VERSION 5.8 ;
BUSBITCHARS "[]" ;
DIVIDERCHAR "/" ;
UNITS
    DATABASE MICRONS 1000 ;
END UNITS

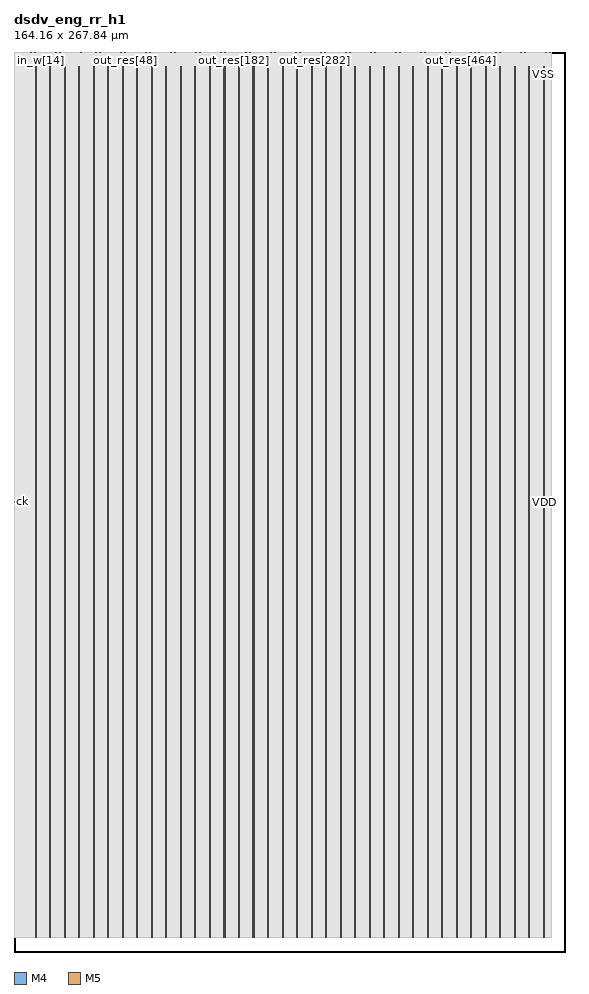
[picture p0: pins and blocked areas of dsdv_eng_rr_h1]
MACRO dsdv_eng_rr_h1
  FOREIGN dsdv_eng_rr_h1 0 0 ;
  CLASS BLOCK ;
  SIZE 164.16 BY 267.84 ;
  PIN ck
    DIRECTION INPUT ;
    USE SIGNAL ;
    PORT
      LAYER M4 ;
        RECT  0 133.92 0.084 133.944 ;
    END
  END ck
  PIN in_w[0]
    DIRECTION INPUT ;
    USE SIGNAL ;
    PORT
      LAYER M5 ;
        RECT  4.8 267.756 4.824 267.84 ;
    END
  END in_w[0]
  PIN in_w[10]
    DIRECTION INPUT ;
    USE SIGNAL ;
    PORT
      LAYER M5 ;
        RECT  7.2 267.756 7.224 267.84 ;
    END
  END in_w[10]
  PIN in_w[11]
    DIRECTION INPUT ;
    USE SIGNAL ;
    PORT
      LAYER M5 ;
        RECT  7.44 267.756 7.464 267.84 ;
    END
  END in_w[11]
  PIN in_w[12]
    DIRECTION INPUT ;
    USE SIGNAL ;
    PORT
      LAYER M5 ;
        RECT  7.68 267.756 7.704 267.84 ;
    END
  END in_w[12]
  PIN in_w[13]
    DIRECTION INPUT ;
    USE SIGNAL ;
    PORT
      LAYER M5 ;
        RECT  7.92 267.756 7.944 267.84 ;
    END
  END in_w[13]
  PIN in_w[14]
    DIRECTION INPUT ;
    USE SIGNAL ;
    PORT
      LAYER M5 ;
        RECT  8.16 267.756 8.184 267.84 ;
    END
  END in_w[14]
  PIN in_w[15]
    DIRECTION INPUT ;
    USE SIGNAL ;
    PORT
      LAYER M5 ;
        RECT  8.4 267.756 8.424 267.84 ;
    END
  END in_w[15]
  PIN in_w[16]
    DIRECTION INPUT ;
    USE SIGNAL ;
    PORT
      LAYER M5 ;
        RECT  8.64 267.756 8.664 267.84 ;
    END
  END in_w[16]
  PIN in_w[17]
    DIRECTION INPUT ;
    USE SIGNAL ;
    PORT
      LAYER M5 ;
        RECT  8.88 267.756 8.904 267.84 ;
    END
  END in_w[17]
  PIN in_w[18]
    DIRECTION INPUT ;
    USE SIGNAL ;
    PORT
      LAYER M5 ;
        RECT  9.12 267.756 9.144 267.84 ;
    END
  END in_w[18]
  PIN in_w[19]
    DIRECTION INPUT ;
    USE SIGNAL ;
    PORT
      LAYER M5 ;
        RECT  9.36 267.756 9.384 267.84 ;
    END
  END in_w[19]
  PIN in_w[1]
    DIRECTION INPUT ;
    USE SIGNAL ;
    PORT
      LAYER M5 ;
        RECT  5.04 267.756 5.064 267.84 ;
    END
  END in_w[1]
  PIN in_w[20]
    DIRECTION INPUT ;
    USE SIGNAL ;
    PORT
      LAYER M5 ;
        RECT  9.6 267.756 9.624 267.84 ;
    END
  END in_w[20]
  PIN in_w[21]
    DIRECTION INPUT ;
    USE SIGNAL ;
    PORT
      LAYER M5 ;
        RECT  9.84 267.756 9.864 267.84 ;
    END
  END in_w[21]
  PIN in_w[22]
    DIRECTION INPUT ;
    USE SIGNAL ;
    PORT
      LAYER M5 ;
        RECT  10.08 267.756 10.104 267.84 ;
    END
  END in_w[22]
  PIN in_w[23]
    DIRECTION INPUT ;
    USE SIGNAL ;
    PORT
      LAYER M5 ;
        RECT  10.32 267.756 10.344 267.84 ;
    END
  END in_w[23]
  PIN in_w[24]
    DIRECTION INPUT ;
    USE SIGNAL ;
    PORT
      LAYER M5 ;
        RECT  10.56 267.756 10.584 267.84 ;
    END
  END in_w[24]
  PIN in_w[25]
    DIRECTION INPUT ;
    USE SIGNAL ;
    PORT
      LAYER M5 ;
        RECT  10.8 267.756 10.824 267.84 ;
    END
  END in_w[25]
  PIN in_w[26]
    DIRECTION INPUT ;
    USE SIGNAL ;
    PORT
      LAYER M5 ;
        RECT  11.04 267.756 11.064 267.84 ;
    END
  END in_w[26]
  PIN in_w[27]
    DIRECTION INPUT ;
    USE SIGNAL ;
    PORT
      LAYER M5 ;
        RECT  11.28 267.756 11.304 267.84 ;
    END
  END in_w[27]
  PIN in_w[28]
    DIRECTION INPUT ;
    USE SIGNAL ;
    PORT
      LAYER M5 ;
        RECT  11.52 267.756 11.544 267.84 ;
    END
  END in_w[28]
  PIN in_w[29]
    DIRECTION INPUT ;
    USE SIGNAL ;
    PORT
      LAYER M5 ;
        RECT  11.76 267.756 11.784 267.84 ;
    END
  END in_w[29]
  PIN in_w[2]
    DIRECTION INPUT ;
    USE SIGNAL ;
    PORT
      LAYER M5 ;
        RECT  5.28 267.756 5.304 267.84 ;
    END
  END in_w[2]
  PIN in_w[30]
    DIRECTION INPUT ;
    USE SIGNAL ;
    PORT
      LAYER M5 ;
        RECT  12 267.756 12.024 267.84 ;
    END
  END in_w[30]
  PIN in_w[31]
    DIRECTION INPUT ;
    USE SIGNAL ;
    PORT
      LAYER M5 ;
        RECT  12.24 267.756 12.264 267.84 ;
    END
  END in_w[31]
  PIN in_w[32]
    DIRECTION INPUT ;
    USE SIGNAL ;
    PORT
      LAYER M5 ;
        RECT  12.48 267.756 12.504 267.84 ;
    END
  END in_w[32]
  PIN in_w[33]
    DIRECTION INPUT ;
    USE SIGNAL ;
    PORT
      LAYER M5 ;
        RECT  12.72 267.756 12.744 267.84 ;
    END
  END in_w[33]
  PIN in_w[34]
    DIRECTION INPUT ;
    USE SIGNAL ;
    PORT
      LAYER M5 ;
        RECT  12.96 267.756 12.984 267.84 ;
    END
  END in_w[34]
  PIN in_w[35]
    DIRECTION INPUT ;
    USE SIGNAL ;
    PORT
      LAYER M5 ;
        RECT  13.2 267.756 13.224 267.84 ;
    END
  END in_w[35]
  PIN in_w[36]
    DIRECTION INPUT ;
    USE SIGNAL ;
    PORT
      LAYER M5 ;
        RECT  13.44 267.756 13.464 267.84 ;
    END
  END in_w[36]
  PIN in_w[37]
    DIRECTION INPUT ;
    USE SIGNAL ;
    PORT
      LAYER M5 ;
        RECT  13.68 267.756 13.704 267.84 ;
    END
  END in_w[37]
  PIN in_w[38]
    DIRECTION INPUT ;
    USE SIGNAL ;
    PORT
      LAYER M5 ;
        RECT  13.92 267.756 13.944 267.84 ;
    END
  END in_w[38]
  PIN in_w[39]
    DIRECTION INPUT ;
    USE SIGNAL ;
    PORT
      LAYER M5 ;
        RECT  14.16 267.756 14.184 267.84 ;
    END
  END in_w[39]
  PIN in_w[3]
    DIRECTION INPUT ;
    USE SIGNAL ;
    PORT
      LAYER M5 ;
        RECT  5.52 267.756 5.544 267.84 ;
    END
  END in_w[3]
  PIN in_w[40]
    DIRECTION INPUT ;
    USE SIGNAL ;
    PORT
      LAYER M5 ;
        RECT  14.4 267.756 14.424 267.84 ;
    END
  END in_w[40]
  PIN in_w[41]
    DIRECTION INPUT ;
    USE SIGNAL ;
    PORT
      LAYER M5 ;
        RECT  14.64 267.756 14.664 267.84 ;
    END
  END in_w[41]
  PIN in_w[42]
    DIRECTION INPUT ;
    USE SIGNAL ;
    PORT
      LAYER M5 ;
        RECT  14.88 267.756 14.904 267.84 ;
    END
  END in_w[42]
  PIN in_w[43]
    DIRECTION INPUT ;
    USE SIGNAL ;
    PORT
      LAYER M5 ;
        RECT  15.12 267.756 15.144 267.84 ;
    END
  END in_w[43]
  PIN in_w[44]
    DIRECTION INPUT ;
    USE SIGNAL ;
    PORT
      LAYER M5 ;
        RECT  15.36 267.756 15.384 267.84 ;
    END
  END in_w[44]
  PIN in_w[45]
    DIRECTION INPUT ;
    USE SIGNAL ;
    PORT
      LAYER M5 ;
        RECT  15.6 267.756 15.624 267.84 ;
    END
  END in_w[45]
  PIN in_w[46]
    DIRECTION INPUT ;
    USE SIGNAL ;
    PORT
      LAYER M5 ;
        RECT  15.84 267.756 15.864 267.84 ;
    END
  END in_w[46]
  PIN in_w[47]
    DIRECTION INPUT ;
    USE SIGNAL ;
    PORT
      LAYER M5 ;
        RECT  16.08 267.756 16.104 267.84 ;
    END
  END in_w[47]
  PIN in_w[48]
    DIRECTION INPUT ;
    USE SIGNAL ;
    PORT
      LAYER M5 ;
        RECT  16.32 267.756 16.344 267.84 ;
    END
  END in_w[48]
  PIN in_w[49]
    DIRECTION INPUT ;
    USE SIGNAL ;
    PORT
      LAYER M5 ;
        RECT  16.56 267.756 16.584 267.84 ;
    END
  END in_w[49]
  PIN in_w[4]
    DIRECTION INPUT ;
    USE SIGNAL ;
    PORT
      LAYER M5 ;
        RECT  5.76 267.756 5.784 267.84 ;
    END
  END in_w[4]
  PIN in_w[50]
    DIRECTION INPUT ;
    USE SIGNAL ;
    PORT
      LAYER M5 ;
        RECT  16.8 267.756 16.824 267.84 ;
    END
  END in_w[50]
  PIN in_w[51]
    DIRECTION INPUT ;
    USE SIGNAL ;
    PORT
      LAYER M5 ;
        RECT  17.04 267.756 17.064 267.84 ;
    END
  END in_w[51]
  PIN in_w[52]
    DIRECTION INPUT ;
    USE SIGNAL ;
    PORT
      LAYER M5 ;
        RECT  17.28 267.756 17.304 267.84 ;
    END
  END in_w[52]
  PIN in_w[53]
    DIRECTION INPUT ;
    USE SIGNAL ;
    PORT
      LAYER M5 ;
        RECT  17.52 267.756 17.544 267.84 ;
    END
  END in_w[53]
  PIN in_w[54]
    DIRECTION INPUT ;
    USE SIGNAL ;
    PORT
      LAYER M5 ;
        RECT  17.76 267.756 17.784 267.84 ;
    END
  END in_w[54]
  PIN in_w[55]
    DIRECTION INPUT ;
    USE SIGNAL ;
    PORT
      LAYER M5 ;
        RECT  18 267.756 18.024 267.84 ;
    END
  END in_w[55]
  PIN in_w[56]
    DIRECTION INPUT ;
    USE SIGNAL ;
    PORT
      LAYER M5 ;
        RECT  18.24 267.756 18.264 267.84 ;
    END
  END in_w[56]
  PIN in_w[57]
    DIRECTION INPUT ;
    USE SIGNAL ;
    PORT
      LAYER M5 ;
        RECT  18.48 267.756 18.504 267.84 ;
    END
  END in_w[57]
  PIN in_w[58]
    DIRECTION INPUT ;
    USE SIGNAL ;
    PORT
      LAYER M5 ;
        RECT  18.72 267.756 18.744 267.84 ;
    END
  END in_w[58]
  PIN in_w[59]
    DIRECTION INPUT ;
    USE SIGNAL ;
    PORT
      LAYER M5 ;
        RECT  18.96 267.756 18.984 267.84 ;
    END
  END in_w[59]
  PIN in_w[5]
    DIRECTION INPUT ;
    USE SIGNAL ;
    PORT
      LAYER M5 ;
        RECT  6 267.756 6.024 267.84 ;
    END
  END in_w[5]
  PIN in_w[60]
    DIRECTION INPUT ;
    USE SIGNAL ;
    PORT
      LAYER M5 ;
        RECT  19.2 267.756 19.224 267.84 ;
    END
  END in_w[60]
  PIN in_w[61]
    DIRECTION INPUT ;
    USE SIGNAL ;
    PORT
      LAYER M5 ;
        RECT  19.44 267.756 19.464 267.84 ;
    END
  END in_w[61]
  PIN in_w[62]
    DIRECTION INPUT ;
    USE SIGNAL ;
    PORT
      LAYER M5 ;
        RECT  19.68 267.756 19.704 267.84 ;
    END
  END in_w[62]
  PIN in_w[63]
    DIRECTION INPUT ;
    USE SIGNAL ;
    PORT
      LAYER M5 ;
        RECT  19.92 267.756 19.944 267.84 ;
    END
  END in_w[63]
  PIN in_w[64]
    DIRECTION INPUT ;
    USE SIGNAL ;
    PORT
      LAYER M5 ;
        RECT  20.16 267.756 20.184 267.84 ;
    END
  END in_w[64]
  PIN in_w[65]
    DIRECTION INPUT ;
    USE SIGNAL ;
    PORT
      LAYER M5 ;
        RECT  20.4 267.756 20.424 267.84 ;
    END
  END in_w[65]
  PIN in_w[66]
    DIRECTION INPUT ;
    USE SIGNAL ;
    PORT
      LAYER M5 ;
        RECT  20.64 267.756 20.664 267.84 ;
    END
  END in_w[66]
  PIN in_w[67]
    DIRECTION INPUT ;
    USE SIGNAL ;
    PORT
      LAYER M5 ;
        RECT  20.88 267.756 20.904 267.84 ;
    END
  END in_w[67]
  PIN in_w[6]
    DIRECTION INPUT ;
    USE SIGNAL ;
    PORT
      LAYER M5 ;
        RECT  6.24 267.756 6.264 267.84 ;
    END
  END in_w[6]
  PIN in_w[7]
    DIRECTION INPUT ;
    USE SIGNAL ;
    PORT
      LAYER M5 ;
        RECT  6.48 267.756 6.504 267.84 ;
    END
  END in_w[7]
  PIN in_w[8]
    DIRECTION INPUT ;
    USE SIGNAL ;
    PORT
      LAYER M5 ;
        RECT  6.72 267.756 6.744 267.84 ;
    END
  END in_w[8]
  PIN in_w[9]
    DIRECTION INPUT ;
    USE SIGNAL ;
    PORT
      LAYER M5 ;
        RECT  6.96 267.756 6.984 267.84 ;
    END
  END in_w[9]
  PIN out_res[0]
    DIRECTION OUTPUT ;
    USE SIGNAL ;
    PORT
      LAYER M5 ;
        RECT  21.744 267.756 21.768 267.84 ;
    END
  END out_res[0]
  PIN out_res[100]
    DIRECTION OUTPUT ;
    USE SIGNAL ;
    PORT
      LAYER M5 ;
        RECT  45.744 267.756 45.768 267.84 ;
    END
  END out_res[100]
  PIN out_res[101]
    DIRECTION OUTPUT ;
    USE SIGNAL ;
    PORT
      LAYER M5 ;
        RECT  45.984 267.756 46.008 267.84 ;
    END
  END out_res[101]
  PIN out_res[102]
    DIRECTION OUTPUT ;
    USE SIGNAL ;
    PORT
      LAYER M5 ;
        RECT  46.224 267.756 46.248 267.84 ;
    END
  END out_res[102]
  PIN out_res[103]
    DIRECTION OUTPUT ;
    USE SIGNAL ;
    PORT
      LAYER M5 ;
        RECT  46.464 267.756 46.488 267.84 ;
    END
  END out_res[103]
  PIN out_res[104]
    DIRECTION OUTPUT ;
    USE SIGNAL ;
    PORT
      LAYER M5 ;
        RECT  46.704 267.756 46.728 267.84 ;
    END
  END out_res[104]
  PIN out_res[105]
    DIRECTION OUTPUT ;
    USE SIGNAL ;
    PORT
      LAYER M5 ;
        RECT  46.944 267.756 46.968 267.84 ;
    END
  END out_res[105]
  PIN out_res[106]
    DIRECTION OUTPUT ;
    USE SIGNAL ;
    PORT
      LAYER M5 ;
        RECT  47.184 267.756 47.208 267.84 ;
    END
  END out_res[106]
  PIN out_res[107]
    DIRECTION OUTPUT ;
    USE SIGNAL ;
    PORT
      LAYER M5 ;
        RECT  47.424 267.756 47.448 267.84 ;
    END
  END out_res[107]
  PIN out_res[108]
    DIRECTION OUTPUT ;
    USE SIGNAL ;
    PORT
      LAYER M5 ;
        RECT  47.664 267.756 47.688 267.84 ;
    END
  END out_res[108]
  PIN out_res[109]
    DIRECTION OUTPUT ;
    USE SIGNAL ;
    PORT
      LAYER M5 ;
        RECT  47.904 267.756 47.928 267.84 ;
    END
  END out_res[109]
  PIN out_res[10]
    DIRECTION OUTPUT ;
    USE SIGNAL ;
    PORT
      LAYER M5 ;
        RECT  24.144 267.756 24.168 267.84 ;
    END
  END out_res[10]
  PIN out_res[110]
    DIRECTION OUTPUT ;
    USE SIGNAL ;
    PORT
      LAYER M5 ;
        RECT  48.144 267.756 48.168 267.84 ;
    END
  END out_res[110]
  PIN out_res[111]
    DIRECTION OUTPUT ;
    USE SIGNAL ;
    PORT
      LAYER M5 ;
        RECT  48.384 267.756 48.408 267.84 ;
    END
  END out_res[111]
  PIN out_res[112]
    DIRECTION OUTPUT ;
    USE SIGNAL ;
    PORT
      LAYER M5 ;
        RECT  48.624 267.756 48.648 267.84 ;
    END
  END out_res[112]
  PIN out_res[113]
    DIRECTION OUTPUT ;
    USE SIGNAL ;
    PORT
      LAYER M5 ;
        RECT  48.864 267.756 48.888 267.84 ;
    END
  END out_res[113]
  PIN out_res[114]
    DIRECTION OUTPUT ;
    USE SIGNAL ;
    PORT
      LAYER M5 ;
        RECT  49.104 267.756 49.128 267.84 ;
    END
  END out_res[114]
  PIN out_res[115]
    DIRECTION OUTPUT ;
    USE SIGNAL ;
    PORT
      LAYER M5 ;
        RECT  49.344 267.756 49.368 267.84 ;
    END
  END out_res[115]
  PIN out_res[116]
    DIRECTION OUTPUT ;
    USE SIGNAL ;
    PORT
      LAYER M5 ;
        RECT  49.584 267.756 49.608 267.84 ;
    END
  END out_res[116]
  PIN out_res[117]
    DIRECTION OUTPUT ;
    USE SIGNAL ;
    PORT
      LAYER M5 ;
        RECT  49.824 267.756 49.848 267.84 ;
    END
  END out_res[117]
  PIN out_res[118]
    DIRECTION OUTPUT ;
    USE SIGNAL ;
    PORT
      LAYER M5 ;
        RECT  50.064 267.756 50.088 267.84 ;
    END
  END out_res[118]
  PIN out_res[119]
    DIRECTION OUTPUT ;
    USE SIGNAL ;
    PORT
      LAYER M5 ;
        RECT  50.304 267.756 50.328 267.84 ;
    END
  END out_res[119]
  PIN out_res[11]
    DIRECTION OUTPUT ;
    USE SIGNAL ;
    PORT
      LAYER M5 ;
        RECT  24.384 267.756 24.408 267.84 ;
    END
  END out_res[11]
  PIN out_res[120]
    DIRECTION OUTPUT ;
    USE SIGNAL ;
    PORT
      LAYER M5 ;
        RECT  50.544 267.756 50.568 267.84 ;
    END
  END out_res[120]
  PIN out_res[121]
    DIRECTION OUTPUT ;
    USE SIGNAL ;
    PORT
      LAYER M5 ;
        RECT  50.784 267.756 50.808 267.84 ;
    END
  END out_res[121]
  PIN out_res[122]
    DIRECTION OUTPUT ;
    USE SIGNAL ;
    PORT
      LAYER M5 ;
        RECT  51.024 267.756 51.048 267.84 ;
    END
  END out_res[122]
  PIN out_res[123]
    DIRECTION OUTPUT ;
    USE SIGNAL ;
    PORT
      LAYER M5 ;
        RECT  51.264 267.756 51.288 267.84 ;
    END
  END out_res[123]
  PIN out_res[124]
    DIRECTION OUTPUT ;
    USE SIGNAL ;
    PORT
      LAYER M5 ;
        RECT  51.504 267.756 51.528 267.84 ;
    END
  END out_res[124]
  PIN out_res[125]
    DIRECTION OUTPUT ;
    USE SIGNAL ;
    PORT
      LAYER M5 ;
        RECT  51.744 267.756 51.768 267.84 ;
    END
  END out_res[125]
  PIN out_res[126]
    DIRECTION OUTPUT ;
    USE SIGNAL ;
    PORT
      LAYER M5 ;
        RECT  51.984 267.756 52.008 267.84 ;
    END
  END out_res[126]
  PIN out_res[127]
    DIRECTION OUTPUT ;
    USE SIGNAL ;
    PORT
      LAYER M5 ;
        RECT  52.224 267.756 52.248 267.84 ;
    END
  END out_res[127]
  PIN out_res[128]
    DIRECTION OUTPUT ;
    USE SIGNAL ;
    PORT
      LAYER M5 ;
        RECT  52.464 267.756 52.488 267.84 ;
    END
  END out_res[128]
  PIN out_res[129]
    DIRECTION OUTPUT ;
    USE SIGNAL ;
    PORT
      LAYER M5 ;
        RECT  52.704 267.756 52.728 267.84 ;
    END
  END out_res[129]
  PIN out_res[12]
    DIRECTION OUTPUT ;
    USE SIGNAL ;
    PORT
      LAYER M5 ;
        RECT  24.624 267.756 24.648 267.84 ;
    END
  END out_res[12]
  PIN out_res[130]
    DIRECTION OUTPUT ;
    USE SIGNAL ;
    PORT
      LAYER M5 ;
        RECT  52.944 267.756 52.968 267.84 ;
    END
  END out_res[130]
  PIN out_res[131]
    DIRECTION OUTPUT ;
    USE SIGNAL ;
    PORT
      LAYER M5 ;
        RECT  53.184 267.756 53.208 267.84 ;
    END
  END out_res[131]
  PIN out_res[132]
    DIRECTION OUTPUT ;
    USE SIGNAL ;
    PORT
      LAYER M5 ;
        RECT  53.424 267.756 53.448 267.84 ;
    END
  END out_res[132]
  PIN out_res[133]
    DIRECTION OUTPUT ;
    USE SIGNAL ;
    PORT
      LAYER M5 ;
        RECT  53.664 267.756 53.688 267.84 ;
    END
  END out_res[133]
  PIN out_res[134]
    DIRECTION OUTPUT ;
    USE SIGNAL ;
    PORT
      LAYER M5 ;
        RECT  53.904 267.756 53.928 267.84 ;
    END
  END out_res[134]
  PIN out_res[135]
    DIRECTION OUTPUT ;
    USE SIGNAL ;
    PORT
      LAYER M5 ;
        RECT  54.144 267.756 54.168 267.84 ;
    END
  END out_res[135]
  PIN out_res[136]
    DIRECTION OUTPUT ;
    USE SIGNAL ;
    PORT
      LAYER M5 ;
        RECT  54.384 267.756 54.408 267.84 ;
    END
  END out_res[136]
  PIN out_res[137]
    DIRECTION OUTPUT ;
    USE SIGNAL ;
    PORT
      LAYER M5 ;
        RECT  54.624 267.756 54.648 267.84 ;
    END
  END out_res[137]
  PIN out_res[138]
    DIRECTION OUTPUT ;
    USE SIGNAL ;
    PORT
      LAYER M5 ;
        RECT  54.864 267.756 54.888 267.84 ;
    END
  END out_res[138]
  PIN out_res[139]
    DIRECTION OUTPUT ;
    USE SIGNAL ;
    PORT
      LAYER M5 ;
        RECT  55.104 267.756 55.128 267.84 ;
    END
  END out_res[139]
  PIN out_res[13]
    DIRECTION OUTPUT ;
    USE SIGNAL ;
    PORT
      LAYER M5 ;
        RECT  24.864 267.756 24.888 267.84 ;
    END
  END out_res[13]
  PIN out_res[140]
    DIRECTION OUTPUT ;
    USE SIGNAL ;
    PORT
      LAYER M5 ;
        RECT  55.344 267.756 55.368 267.84 ;
    END
  END out_res[140]
  PIN out_res[141]
    DIRECTION OUTPUT ;
    USE SIGNAL ;
    PORT
      LAYER M5 ;
        RECT  55.584 267.756 55.608 267.84 ;
    END
  END out_res[141]
  PIN out_res[142]
    DIRECTION OUTPUT ;
    USE SIGNAL ;
    PORT
      LAYER M5 ;
        RECT  55.824 267.756 55.848 267.84 ;
    END
  END out_res[142]
  PIN out_res[143]
    DIRECTION OUTPUT ;
    USE SIGNAL ;
    PORT
      LAYER M5 ;
        RECT  56.064 267.756 56.088 267.84 ;
    END
  END out_res[143]
  PIN out_res[144]
    DIRECTION OUTPUT ;
    USE SIGNAL ;
    PORT
      LAYER M5 ;
        RECT  56.304 267.756 56.328 267.84 ;
    END
  END out_res[144]
  PIN out_res[145]
    DIRECTION OUTPUT ;
    USE SIGNAL ;
    PORT
      LAYER M5 ;
        RECT  56.544 267.756 56.568 267.84 ;
    END
  END out_res[145]
  PIN out_res[146]
    DIRECTION OUTPUT ;
    USE SIGNAL ;
    PORT
      LAYER M5 ;
        RECT  56.784 267.756 56.808 267.84 ;
    END
  END out_res[146]
  PIN out_res[147]
    DIRECTION OUTPUT ;
    USE SIGNAL ;
    PORT
      LAYER M5 ;
        RECT  57.024 267.756 57.048 267.84 ;
    END
  END out_res[147]
  PIN out_res[148]
    DIRECTION OUTPUT ;
    USE SIGNAL ;
    PORT
      LAYER M5 ;
        RECT  57.264 267.756 57.288 267.84 ;
    END
  END out_res[148]
  PIN out_res[149]
    DIRECTION OUTPUT ;
    USE SIGNAL ;
    PORT
      LAYER M5 ;
        RECT  57.504 267.756 57.528 267.84 ;
    END
  END out_res[149]
  PIN out_res[14]
    DIRECTION OUTPUT ;
    USE SIGNAL ;
    PORT
      LAYER M5 ;
        RECT  25.104 267.756 25.128 267.84 ;
    END
  END out_res[14]
  PIN out_res[150]
    DIRECTION OUTPUT ;
    USE SIGNAL ;
    PORT
      LAYER M5 ;
        RECT  57.744 267.756 57.768 267.84 ;
    END
  END out_res[150]
  PIN out_res[151]
    DIRECTION OUTPUT ;
    USE SIGNAL ;
    PORT
      LAYER M5 ;
        RECT  57.984 267.756 58.008 267.84 ;
    END
  END out_res[151]
  PIN out_res[152]
    DIRECTION OUTPUT ;
    USE SIGNAL ;
    PORT
      LAYER M5 ;
        RECT  58.224 267.756 58.248 267.84 ;
    END
  END out_res[152]
  PIN out_res[153]
    DIRECTION OUTPUT ;
    USE SIGNAL ;
    PORT
      LAYER M5 ;
        RECT  58.464 267.756 58.488 267.84 ;
    END
  END out_res[153]
  PIN out_res[154]
    DIRECTION OUTPUT ;
    USE SIGNAL ;
    PORT
      LAYER M5 ;
        RECT  58.704 267.756 58.728 267.84 ;
    END
  END out_res[154]
  PIN out_res[155]
    DIRECTION OUTPUT ;
    USE SIGNAL ;
    PORT
      LAYER M5 ;
        RECT  58.944 267.756 58.968 267.84 ;
    END
  END out_res[155]
  PIN out_res[156]
    DIRECTION OUTPUT ;
    USE SIGNAL ;
    PORT
      LAYER M5 ;
        RECT  59.184 267.756 59.208 267.84 ;
    END
  END out_res[156]
  PIN out_res[157]
    DIRECTION OUTPUT ;
    USE SIGNAL ;
    PORT
      LAYER M5 ;
        RECT  59.424 267.756 59.448 267.84 ;
    END
  END out_res[157]
  PIN out_res[158]
    DIRECTION OUTPUT ;
    USE SIGNAL ;
    PORT
      LAYER M5 ;
        RECT  59.664 267.756 59.688 267.84 ;
    END
  END out_res[158]
  PIN out_res[159]
    DIRECTION OUTPUT ;
    USE SIGNAL ;
    PORT
      LAYER M5 ;
        RECT  59.904 267.756 59.928 267.84 ;
    END
  END out_res[159]
  PIN out_res[15]
    DIRECTION OUTPUT ;
    USE SIGNAL ;
    PORT
      LAYER M5 ;
        RECT  25.344 267.756 25.368 267.84 ;
    END
  END out_res[15]
  PIN out_res[160]
    DIRECTION OUTPUT ;
    USE SIGNAL ;
    PORT
      LAYER M5 ;
        RECT  60.144 267.756 60.168 267.84 ;
    END
  END out_res[160]
  PIN out_res[161]
    DIRECTION OUTPUT ;
    USE SIGNAL ;
    PORT
      LAYER M5 ;
        RECT  60.384 267.756 60.408 267.84 ;
    END
  END out_res[161]
  PIN out_res[162]
    DIRECTION OUTPUT ;
    USE SIGNAL ;
    PORT
      LAYER M5 ;
        RECT  60.624 267.756 60.648 267.84 ;
    END
  END out_res[162]
  PIN out_res[163]
    DIRECTION OUTPUT ;
    USE SIGNAL ;
    PORT
      LAYER M5 ;
        RECT  60.864 267.756 60.888 267.84 ;
    END
  END out_res[163]
  PIN out_res[164]
    DIRECTION OUTPUT ;
    USE SIGNAL ;
    PORT
      LAYER M5 ;
        RECT  61.104 267.756 61.128 267.84 ;
    END
  END out_res[164]
  PIN out_res[165]
    DIRECTION OUTPUT ;
    USE SIGNAL ;
    PORT
      LAYER M5 ;
        RECT  61.344 267.756 61.368 267.84 ;
    END
  END out_res[165]
  PIN out_res[166]
    DIRECTION OUTPUT ;
    USE SIGNAL ;
    PORT
      LAYER M5 ;
        RECT  61.584 267.756 61.608 267.84 ;
    END
  END out_res[166]
  PIN out_res[167]
    DIRECTION OUTPUT ;
    USE SIGNAL ;
    PORT
      LAYER M5 ;
        RECT  61.824 267.756 61.848 267.84 ;
    END
  END out_res[167]
  PIN out_res[168]
    DIRECTION OUTPUT ;
    USE SIGNAL ;
    PORT
      LAYER M5 ;
        RECT  62.064 267.756 62.088 267.84 ;
    END
  END out_res[168]
  PIN out_res[169]
    DIRECTION OUTPUT ;
    USE SIGNAL ;
    PORT
      LAYER M5 ;
        RECT  62.304 267.756 62.328 267.84 ;
    END
  END out_res[169]
  PIN out_res[16]
    DIRECTION OUTPUT ;
    USE SIGNAL ;
    PORT
      LAYER M5 ;
        RECT  25.584 267.756 25.608 267.84 ;
    END
  END out_res[16]
  PIN out_res[170]
    DIRECTION OUTPUT ;
    USE SIGNAL ;
    PORT
      LAYER M5 ;
        RECT  62.544 267.756 62.568 267.84 ;
    END
  END out_res[170]
  PIN out_res[171]
    DIRECTION OUTPUT ;
    USE SIGNAL ;
    PORT
      LAYER M5 ;
        RECT  62.784 267.756 62.808 267.84 ;
    END
  END out_res[171]
  PIN out_res[172]
    DIRECTION OUTPUT ;
    USE SIGNAL ;
    PORT
      LAYER M5 ;
        RECT  63.024 267.756 63.048 267.84 ;
    END
  END out_res[172]
  PIN out_res[173]
    DIRECTION OUTPUT ;
    USE SIGNAL ;
    PORT
      LAYER M5 ;
        RECT  63.264 267.756 63.288 267.84 ;
    END
  END out_res[173]
  PIN out_res[174]
    DIRECTION OUTPUT ;
    USE SIGNAL ;
    PORT
      LAYER M5 ;
        RECT  63.504 267.756 63.528 267.84 ;
    END
  END out_res[174]
  PIN out_res[175]
    DIRECTION OUTPUT ;
    USE SIGNAL ;
    PORT
      LAYER M5 ;
        RECT  63.744 267.756 63.768 267.84 ;
    END
  END out_res[175]
  PIN out_res[176]
    DIRECTION OUTPUT ;
    USE SIGNAL ;
    PORT
      LAYER M5 ;
        RECT  63.984 267.756 64.008 267.84 ;
    END
  END out_res[176]
  PIN out_res[177]
    DIRECTION OUTPUT ;
    USE SIGNAL ;
    PORT
      LAYER M5 ;
        RECT  64.224 267.756 64.248 267.84 ;
    END
  END out_res[177]
  PIN out_res[178]
    DIRECTION OUTPUT ;
    USE SIGNAL ;
    PORT
      LAYER M5 ;
        RECT  64.464 267.756 64.488 267.84 ;
    END
  END out_res[178]
  PIN out_res[179]
    DIRECTION OUTPUT ;
    USE SIGNAL ;
    PORT
      LAYER M5 ;
        RECT  64.704 267.756 64.728 267.84 ;
    END
  END out_res[179]
  PIN out_res[17]
    DIRECTION OUTPUT ;
    USE SIGNAL ;
    PORT
      LAYER M5 ;
        RECT  25.824 267.756 25.848 267.84 ;
    END
  END out_res[17]
  PIN out_res[180]
    DIRECTION OUTPUT ;
    USE SIGNAL ;
    PORT
      LAYER M5 ;
        RECT  64.944 267.756 64.968 267.84 ;
    END
  END out_res[180]
  PIN out_res[181]
    DIRECTION OUTPUT ;
    USE SIGNAL ;
    PORT
      LAYER M5 ;
        RECT  65.184 267.756 65.208 267.84 ;
    END
  END out_res[181]
  PIN out_res[182]
    DIRECTION OUTPUT ;
    USE SIGNAL ;
    PORT
      LAYER M5 ;
        RECT  65.424 267.756 65.448 267.84 ;
    END
  END out_res[182]
  PIN out_res[183]
    DIRECTION OUTPUT ;
    USE SIGNAL ;
    PORT
      LAYER M5 ;
        RECT  65.664 267.756 65.688 267.84 ;
    END
  END out_res[183]
  PIN out_res[184]
    DIRECTION OUTPUT ;
    USE SIGNAL ;
    PORT
      LAYER M5 ;
        RECT  65.904 267.756 65.928 267.84 ;
    END
  END out_res[184]
  PIN out_res[185]
    DIRECTION OUTPUT ;
    USE SIGNAL ;
    PORT
      LAYER M5 ;
        RECT  66.144 267.756 66.168 267.84 ;
    END
  END out_res[185]
  PIN out_res[186]
    DIRECTION OUTPUT ;
    USE SIGNAL ;
    PORT
      LAYER M5 ;
        RECT  66.384 267.756 66.408 267.84 ;
    END
  END out_res[186]
  PIN out_res[187]
    DIRECTION OUTPUT ;
    USE SIGNAL ;
    PORT
      LAYER M5 ;
        RECT  66.624 267.756 66.648 267.84 ;
    END
  END out_res[187]
  PIN out_res[188]
    DIRECTION OUTPUT ;
    USE SIGNAL ;
    PORT
      LAYER M5 ;
        RECT  66.864 267.756 66.888 267.84 ;
    END
  END out_res[188]
  PIN out_res[189]
    DIRECTION OUTPUT ;
    USE SIGNAL ;
    PORT
      LAYER M5 ;
        RECT  67.104 267.756 67.128 267.84 ;
    END
  END out_res[189]
  PIN out_res[18]
    DIRECTION OUTPUT ;
    USE SIGNAL ;
    PORT
      LAYER M5 ;
        RECT  26.064 267.756 26.088 267.84 ;
    END
  END out_res[18]
  PIN out_res[190]
    DIRECTION OUTPUT ;
    USE SIGNAL ;
    PORT
      LAYER M5 ;
        RECT  67.344 267.756 67.368 267.84 ;
    END
  END out_res[190]
  PIN out_res[191]
    DIRECTION OUTPUT ;
    USE SIGNAL ;
    PORT
      LAYER M5 ;
        RECT  67.584 267.756 67.608 267.84 ;
    END
  END out_res[191]
  PIN out_res[192]
    DIRECTION OUTPUT ;
    USE SIGNAL ;
    PORT
      LAYER M5 ;
        RECT  67.824 267.756 67.848 267.84 ;
    END
  END out_res[192]
  PIN out_res[193]
    DIRECTION OUTPUT ;
    USE SIGNAL ;
    PORT
      LAYER M5 ;
        RECT  68.064 267.756 68.088 267.84 ;
    END
  END out_res[193]
  PIN out_res[194]
    DIRECTION OUTPUT ;
    USE SIGNAL ;
    PORT
      LAYER M5 ;
        RECT  68.304 267.756 68.328 267.84 ;
    END
  END out_res[194]
  PIN out_res[195]
    DIRECTION OUTPUT ;
    USE SIGNAL ;
    PORT
      LAYER M5 ;
        RECT  68.544 267.756 68.568 267.84 ;
    END
  END out_res[195]
  PIN out_res[196]
    DIRECTION OUTPUT ;
    USE SIGNAL ;
    PORT
      LAYER M5 ;
        RECT  68.784 267.756 68.808 267.84 ;
    END
  END out_res[196]
  PIN out_res[197]
    DIRECTION OUTPUT ;
    USE SIGNAL ;
    PORT
      LAYER M5 ;
        RECT  69.024 267.756 69.048 267.84 ;
    END
  END out_res[197]
  PIN out_res[198]
    DIRECTION OUTPUT ;
    USE SIGNAL ;
    PORT
      LAYER M5 ;
        RECT  69.264 267.756 69.288 267.84 ;
    END
  END out_res[198]
  PIN out_res[199]
    DIRECTION OUTPUT ;
    USE SIGNAL ;
    PORT
      LAYER M5 ;
        RECT  69.504 267.756 69.528 267.84 ;
    END
  END out_res[199]
  PIN out_res[19]
    DIRECTION OUTPUT ;
    USE SIGNAL ;
    PORT
      LAYER M5 ;
        RECT  26.304 267.756 26.328 267.84 ;
    END
  END out_res[19]
  PIN out_res[1]
    DIRECTION OUTPUT ;
    USE SIGNAL ;
    PORT
      LAYER M5 ;
        RECT  21.984 267.756 22.008 267.84 ;
    END
  END out_res[1]
  PIN out_res[200]
    DIRECTION OUTPUT ;
    USE SIGNAL ;
    PORT
      LAYER M5 ;
        RECT  69.744 267.756 69.768 267.84 ;
    END
  END out_res[200]
  PIN out_res[201]
    DIRECTION OUTPUT ;
    USE SIGNAL ;
    PORT
      LAYER M5 ;
        RECT  69.984 267.756 70.008 267.84 ;
    END
  END out_res[201]
  PIN out_res[202]
    DIRECTION OUTPUT ;
    USE SIGNAL ;
    PORT
      LAYER M5 ;
        RECT  70.224 267.756 70.248 267.84 ;
    END
  END out_res[202]
  PIN out_res[203]
    DIRECTION OUTPUT ;
    USE SIGNAL ;
    PORT
      LAYER M5 ;
        RECT  70.464 267.756 70.488 267.84 ;
    END
  END out_res[203]
  PIN out_res[204]
    DIRECTION OUTPUT ;
    USE SIGNAL ;
    PORT
      LAYER M5 ;
        RECT  70.704 267.756 70.728 267.84 ;
    END
  END out_res[204]
  PIN out_res[205]
    DIRECTION OUTPUT ;
    USE SIGNAL ;
    PORT
      LAYER M5 ;
        RECT  70.944 267.756 70.968 267.84 ;
    END
  END out_res[205]
  PIN out_res[206]
    DIRECTION OUTPUT ;
    USE SIGNAL ;
    PORT
      LAYER M5 ;
        RECT  71.184 267.756 71.208 267.84 ;
    END
  END out_res[206]
  PIN out_res[207]
    DIRECTION OUTPUT ;
    USE SIGNAL ;
    PORT
      LAYER M5 ;
        RECT  71.424 267.756 71.448 267.84 ;
    END
  END out_res[207]
  PIN out_res[208]
    DIRECTION OUTPUT ;
    USE SIGNAL ;
    PORT
      LAYER M5 ;
        RECT  71.664 267.756 71.688 267.84 ;
    END
  END out_res[208]
  PIN out_res[209]
    DIRECTION OUTPUT ;
    USE SIGNAL ;
    PORT
      LAYER M5 ;
        RECT  71.904 267.756 71.928 267.84 ;
    END
  END out_res[209]
  PIN out_res[20]
    DIRECTION OUTPUT ;
    USE SIGNAL ;
    PORT
      LAYER M5 ;
        RECT  26.544 267.756 26.568 267.84 ;
    END
  END out_res[20]
  PIN out_res[210]
    DIRECTION OUTPUT ;
    USE SIGNAL ;
    PORT
      LAYER M5 ;
        RECT  72.144 267.756 72.168 267.84 ;
    END
  END out_res[210]
  PIN out_res[211]
    DIRECTION OUTPUT ;
    USE SIGNAL ;
    PORT
      LAYER M5 ;
        RECT  72.384 267.756 72.408 267.84 ;
    END
  END out_res[211]
  PIN out_res[212]
    DIRECTION OUTPUT ;
    USE SIGNAL ;
    PORT
      LAYER M5 ;
        RECT  72.624 267.756 72.648 267.84 ;
    END
  END out_res[212]
  PIN out_res[213]
    DIRECTION OUTPUT ;
    USE SIGNAL ;
    PORT
      LAYER M5 ;
        RECT  72.864 267.756 72.888 267.84 ;
    END
  END out_res[213]
  PIN out_res[214]
    DIRECTION OUTPUT ;
    USE SIGNAL ;
    PORT
      LAYER M5 ;
        RECT  73.104 267.756 73.128 267.84 ;
    END
  END out_res[214]
  PIN out_res[215]
    DIRECTION OUTPUT ;
    USE SIGNAL ;
    PORT
      LAYER M5 ;
        RECT  73.344 267.756 73.368 267.84 ;
    END
  END out_res[215]
  PIN out_res[216]
    DIRECTION OUTPUT ;
    USE SIGNAL ;
    PORT
      LAYER M5 ;
        RECT  73.584 267.756 73.608 267.84 ;
    END
  END out_res[216]
  PIN out_res[217]
    DIRECTION OUTPUT ;
    USE SIGNAL ;
    PORT
      LAYER M5 ;
        RECT  73.824 267.756 73.848 267.84 ;
    END
  END out_res[217]
  PIN out_res[218]
    DIRECTION OUTPUT ;
    USE SIGNAL ;
    PORT
      LAYER M5 ;
        RECT  74.064 267.756 74.088 267.84 ;
    END
  END out_res[218]
  PIN out_res[219]
    DIRECTION OUTPUT ;
    USE SIGNAL ;
    PORT
      LAYER M5 ;
        RECT  74.304 267.756 74.328 267.84 ;
    END
  END out_res[219]
  PIN out_res[21]
    DIRECTION OUTPUT ;
    USE SIGNAL ;
    PORT
      LAYER M5 ;
        RECT  26.784 267.756 26.808 267.84 ;
    END
  END out_res[21]
  PIN out_res[220]
    DIRECTION OUTPUT ;
    USE SIGNAL ;
    PORT
      LAYER M5 ;
        RECT  74.544 267.756 74.568 267.84 ;
    END
  END out_res[220]
  PIN out_res[221]
    DIRECTION OUTPUT ;
    USE SIGNAL ;
    PORT
      LAYER M5 ;
        RECT  74.784 267.756 74.808 267.84 ;
    END
  END out_res[221]
  PIN out_res[222]
    DIRECTION OUTPUT ;
    USE SIGNAL ;
    PORT
      LAYER M5 ;
        RECT  75.024 267.756 75.048 267.84 ;
    END
  END out_res[222]
  PIN out_res[223]
    DIRECTION OUTPUT ;
    USE SIGNAL ;
    PORT
      LAYER M5 ;
        RECT  75.264 267.756 75.288 267.84 ;
    END
  END out_res[223]
  PIN out_res[224]
    DIRECTION OUTPUT ;
    USE SIGNAL ;
    PORT
      LAYER M5 ;
        RECT  75.504 267.756 75.528 267.84 ;
    END
  END out_res[224]
  PIN out_res[225]
    DIRECTION OUTPUT ;
    USE SIGNAL ;
    PORT
      LAYER M5 ;
        RECT  75.744 267.756 75.768 267.84 ;
    END
  END out_res[225]
  PIN out_res[226]
    DIRECTION OUTPUT ;
    USE SIGNAL ;
    PORT
      LAYER M5 ;
        RECT  75.984 267.756 76.008 267.84 ;
    END
  END out_res[226]
  PIN out_res[227]
    DIRECTION OUTPUT ;
    USE SIGNAL ;
    PORT
      LAYER M5 ;
        RECT  76.224 267.756 76.248 267.84 ;
    END
  END out_res[227]
  PIN out_res[228]
    DIRECTION OUTPUT ;
    USE SIGNAL ;
    PORT
      LAYER M5 ;
        RECT  76.464 267.756 76.488 267.84 ;
    END
  END out_res[228]
  PIN out_res[229]
    DIRECTION OUTPUT ;
    USE SIGNAL ;
    PORT
      LAYER M5 ;
        RECT  76.704 267.756 76.728 267.84 ;
    END
  END out_res[229]
  PIN out_res[22]
    DIRECTION OUTPUT ;
    USE SIGNAL ;
    PORT
      LAYER M5 ;
        RECT  27.024 267.756 27.048 267.84 ;
    END
  END out_res[22]
  PIN out_res[230]
    DIRECTION OUTPUT ;
    USE SIGNAL ;
    PORT
      LAYER M5 ;
        RECT  76.944 267.756 76.968 267.84 ;
    END
  END out_res[230]
  PIN out_res[231]
    DIRECTION OUTPUT ;
    USE SIGNAL ;
    PORT
      LAYER M5 ;
        RECT  77.184 267.756 77.208 267.84 ;
    END
  END out_res[231]
  PIN out_res[232]
    DIRECTION OUTPUT ;
    USE SIGNAL ;
    PORT
      LAYER M5 ;
        RECT  77.424 267.756 77.448 267.84 ;
    END
  END out_res[232]
  PIN out_res[233]
    DIRECTION OUTPUT ;
    USE SIGNAL ;
    PORT
      LAYER M5 ;
        RECT  77.664 267.756 77.688 267.84 ;
    END
  END out_res[233]
  PIN out_res[234]
    DIRECTION OUTPUT ;
    USE SIGNAL ;
    PORT
      LAYER M5 ;
        RECT  77.904 267.756 77.928 267.84 ;
    END
  END out_res[234]
  PIN out_res[235]
    DIRECTION OUTPUT ;
    USE SIGNAL ;
    PORT
      LAYER M5 ;
        RECT  78.144 267.756 78.168 267.84 ;
    END
  END out_res[235]
  PIN out_res[236]
    DIRECTION OUTPUT ;
    USE SIGNAL ;
    PORT
      LAYER M5 ;
        RECT  78.384 267.756 78.408 267.84 ;
    END
  END out_res[236]
  PIN out_res[237]
    DIRECTION OUTPUT ;
    USE SIGNAL ;
    PORT
      LAYER M5 ;
        RECT  78.624 267.756 78.648 267.84 ;
    END
  END out_res[237]
  PIN out_res[238]
    DIRECTION OUTPUT ;
    USE SIGNAL ;
    PORT
      LAYER M5 ;
        RECT  78.864 267.756 78.888 267.84 ;
    END
  END out_res[238]
  PIN out_res[239]
    DIRECTION OUTPUT ;
    USE SIGNAL ;
    PORT
      LAYER M5 ;
        RECT  79.104 267.756 79.128 267.84 ;
    END
  END out_res[239]
  PIN out_res[23]
    DIRECTION OUTPUT ;
    USE SIGNAL ;
    PORT
      LAYER M5 ;
        RECT  27.264 267.756 27.288 267.84 ;
    END
  END out_res[23]
  PIN out_res[240]
    DIRECTION OUTPUT ;
    USE SIGNAL ;
    PORT
      LAYER M5 ;
        RECT  79.344 267.756 79.368 267.84 ;
    END
  END out_res[240]
  PIN out_res[241]
    DIRECTION OUTPUT ;
    USE SIGNAL ;
    PORT
      LAYER M5 ;
        RECT  79.584 267.756 79.608 267.84 ;
    END
  END out_res[241]
  PIN out_res[242]
    DIRECTION OUTPUT ;
    USE SIGNAL ;
    PORT
      LAYER M5 ;
        RECT  79.824 267.756 79.848 267.84 ;
    END
  END out_res[242]
  PIN out_res[243]
    DIRECTION OUTPUT ;
    USE SIGNAL ;
    PORT
      LAYER M5 ;
        RECT  80.064 267.756 80.088 267.84 ;
    END
  END out_res[243]
  PIN out_res[244]
    DIRECTION OUTPUT ;
    USE SIGNAL ;
    PORT
      LAYER M5 ;
        RECT  80.304 267.756 80.328 267.84 ;
    END
  END out_res[244]
  PIN out_res[245]
    DIRECTION OUTPUT ;
    USE SIGNAL ;
    PORT
      LAYER M5 ;
        RECT  80.544 267.756 80.568 267.84 ;
    END
  END out_res[245]
  PIN out_res[246]
    DIRECTION OUTPUT ;
    USE SIGNAL ;
    PORT
      LAYER M5 ;
        RECT  80.784 267.756 80.808 267.84 ;
    END
  END out_res[246]
  PIN out_res[247]
    DIRECTION OUTPUT ;
    USE SIGNAL ;
    PORT
      LAYER M5 ;
        RECT  81.024 267.756 81.048 267.84 ;
    END
  END out_res[247]
  PIN out_res[248]
    DIRECTION OUTPUT ;
    USE SIGNAL ;
    PORT
      LAYER M5 ;
        RECT  81.264 267.756 81.288 267.84 ;
    END
  END out_res[248]
  PIN out_res[249]
    DIRECTION OUTPUT ;
    USE SIGNAL ;
    PORT
      LAYER M5 ;
        RECT  81.504 267.756 81.528 267.84 ;
    END
  END out_res[249]
  PIN out_res[24]
    DIRECTION OUTPUT ;
    USE SIGNAL ;
    PORT
      LAYER M5 ;
        RECT  27.504 267.756 27.528 267.84 ;
    END
  END out_res[24]
  PIN out_res[250]
    DIRECTION OUTPUT ;
    USE SIGNAL ;
    PORT
      LAYER M5 ;
        RECT  81.744 267.756 81.768 267.84 ;
    END
  END out_res[250]
  PIN out_res[251]
    DIRECTION OUTPUT ;
    USE SIGNAL ;
    PORT
      LAYER M5 ;
        RECT  81.984 267.756 82.008 267.84 ;
    END
  END out_res[251]
  PIN out_res[252]
    DIRECTION OUTPUT ;
    USE SIGNAL ;
    PORT
      LAYER M5 ;
        RECT  82.224 267.756 82.248 267.84 ;
    END
  END out_res[252]
  PIN out_res[253]
    DIRECTION OUTPUT ;
    USE SIGNAL ;
    PORT
      LAYER M5 ;
        RECT  82.464 267.756 82.488 267.84 ;
    END
  END out_res[253]
  PIN out_res[254]
    DIRECTION OUTPUT ;
    USE SIGNAL ;
    PORT
      LAYER M5 ;
        RECT  82.704 267.756 82.728 267.84 ;
    END
  END out_res[254]
  PIN out_res[255]
    DIRECTION OUTPUT ;
    USE SIGNAL ;
    PORT
      LAYER M5 ;
        RECT  82.944 267.756 82.968 267.84 ;
    END
  END out_res[255]
  PIN out_res[256]
    DIRECTION OUTPUT ;
    USE SIGNAL ;
    PORT
      LAYER M5 ;
        RECT  83.184 267.756 83.208 267.84 ;
    END
  END out_res[256]
  PIN out_res[257]
    DIRECTION OUTPUT ;
    USE SIGNAL ;
    PORT
      LAYER M5 ;
        RECT  83.424 267.756 83.448 267.84 ;
    END
  END out_res[257]
  PIN out_res[258]
    DIRECTION OUTPUT ;
    USE SIGNAL ;
    PORT
      LAYER M5 ;
        RECT  83.664 267.756 83.688 267.84 ;
    END
  END out_res[258]
  PIN out_res[259]
    DIRECTION OUTPUT ;
    USE SIGNAL ;
    PORT
      LAYER M5 ;
        RECT  83.904 267.756 83.928 267.84 ;
    END
  END out_res[259]
  PIN out_res[25]
    DIRECTION OUTPUT ;
    USE SIGNAL ;
    PORT
      LAYER M5 ;
        RECT  27.744 267.756 27.768 267.84 ;
    END
  END out_res[25]
  PIN out_res[260]
    DIRECTION OUTPUT ;
    USE SIGNAL ;
    PORT
      LAYER M5 ;
        RECT  84.144 267.756 84.168 267.84 ;
    END
  END out_res[260]
  PIN out_res[261]
    DIRECTION OUTPUT ;
    USE SIGNAL ;
    PORT
      LAYER M5 ;
        RECT  84.384 267.756 84.408 267.84 ;
    END
  END out_res[261]
  PIN out_res[262]
    DIRECTION OUTPUT ;
    USE SIGNAL ;
    PORT
      LAYER M5 ;
        RECT  84.624 267.756 84.648 267.84 ;
    END
  END out_res[262]
  PIN out_res[263]
    DIRECTION OUTPUT ;
    USE SIGNAL ;
    PORT
      LAYER M5 ;
        RECT  84.864 267.756 84.888 267.84 ;
    END
  END out_res[263]
  PIN out_res[264]
    DIRECTION OUTPUT ;
    USE SIGNAL ;
    PORT
      LAYER M5 ;
        RECT  85.104 267.756 85.128 267.84 ;
    END
  END out_res[264]
  PIN out_res[265]
    DIRECTION OUTPUT ;
    USE SIGNAL ;
    PORT
      LAYER M5 ;
        RECT  85.344 267.756 85.368 267.84 ;
    END
  END out_res[265]
  PIN out_res[266]
    DIRECTION OUTPUT ;
    USE SIGNAL ;
    PORT
      LAYER M5 ;
        RECT  85.584 267.756 85.608 267.84 ;
    END
  END out_res[266]
  PIN out_res[267]
    DIRECTION OUTPUT ;
    USE SIGNAL ;
    PORT
      LAYER M5 ;
        RECT  85.824 267.756 85.848 267.84 ;
    END
  END out_res[267]
  PIN out_res[268]
    DIRECTION OUTPUT ;
    USE SIGNAL ;
    PORT
      LAYER M5 ;
        RECT  86.064 267.756 86.088 267.84 ;
    END
  END out_res[268]
  PIN out_res[269]
    DIRECTION OUTPUT ;
    USE SIGNAL ;
    PORT
      LAYER M5 ;
        RECT  86.304 267.756 86.328 267.84 ;
    END
  END out_res[269]
  PIN out_res[26]
    DIRECTION OUTPUT ;
    USE SIGNAL ;
    PORT
      LAYER M5 ;
        RECT  27.984 267.756 28.008 267.84 ;
    END
  END out_res[26]
  PIN out_res[270]
    DIRECTION OUTPUT ;
    USE SIGNAL ;
    PORT
      LAYER M5 ;
        RECT  86.544 267.756 86.568 267.84 ;
    END
  END out_res[270]
  PIN out_res[271]
    DIRECTION OUTPUT ;
    USE SIGNAL ;
    PORT
      LAYER M5 ;
        RECT  86.784 267.756 86.808 267.84 ;
    END
  END out_res[271]
  PIN out_res[272]
    DIRECTION OUTPUT ;
    USE SIGNAL ;
    PORT
      LAYER M5 ;
        RECT  87.024 267.756 87.048 267.84 ;
    END
  END out_res[272]
  PIN out_res[273]
    DIRECTION OUTPUT ;
    USE SIGNAL ;
    PORT
      LAYER M5 ;
        RECT  87.264 267.756 87.288 267.84 ;
    END
  END out_res[273]
  PIN out_res[274]
    DIRECTION OUTPUT ;
    USE SIGNAL ;
    PORT
      LAYER M5 ;
        RECT  87.504 267.756 87.528 267.84 ;
    END
  END out_res[274]
  PIN out_res[275]
    DIRECTION OUTPUT ;
    USE SIGNAL ;
    PORT
      LAYER M5 ;
        RECT  87.744 267.756 87.768 267.84 ;
    END
  END out_res[275]
  PIN out_res[276]
    DIRECTION OUTPUT ;
    USE SIGNAL ;
    PORT
      LAYER M5 ;
        RECT  87.984 267.756 88.008 267.84 ;
    END
  END out_res[276]
  PIN out_res[277]
    DIRECTION OUTPUT ;
    USE SIGNAL ;
    PORT
      LAYER M5 ;
        RECT  88.224 267.756 88.248 267.84 ;
    END
  END out_res[277]
  PIN out_res[278]
    DIRECTION OUTPUT ;
    USE SIGNAL ;
    PORT
      LAYER M5 ;
        RECT  88.464 267.756 88.488 267.84 ;
    END
  END out_res[278]
  PIN out_res[279]
    DIRECTION OUTPUT ;
    USE SIGNAL ;
    PORT
      LAYER M5 ;
        RECT  88.704 267.756 88.728 267.84 ;
    END
  END out_res[279]
  PIN out_res[27]
    DIRECTION OUTPUT ;
    USE SIGNAL ;
    PORT
      LAYER M5 ;
        RECT  28.224 267.756 28.248 267.84 ;
    END
  END out_res[27]
  PIN out_res[280]
    DIRECTION OUTPUT ;
    USE SIGNAL ;
    PORT
      LAYER M5 ;
        RECT  88.944 267.756 88.968 267.84 ;
    END
  END out_res[280]
  PIN out_res[281]
    DIRECTION OUTPUT ;
    USE SIGNAL ;
    PORT
      LAYER M5 ;
        RECT  89.184 267.756 89.208 267.84 ;
    END
  END out_res[281]
  PIN out_res[282]
    DIRECTION OUTPUT ;
    USE SIGNAL ;
    PORT
      LAYER M5 ;
        RECT  89.424 267.756 89.448 267.84 ;
    END
  END out_res[282]
  PIN out_res[283]
    DIRECTION OUTPUT ;
    USE SIGNAL ;
    PORT
      LAYER M5 ;
        RECT  89.664 267.756 89.688 267.84 ;
    END
  END out_res[283]
  PIN out_res[284]
    DIRECTION OUTPUT ;
    USE SIGNAL ;
    PORT
      LAYER M5 ;
        RECT  89.904 267.756 89.928 267.84 ;
    END
  END out_res[284]
  PIN out_res[285]
    DIRECTION OUTPUT ;
    USE SIGNAL ;
    PORT
      LAYER M5 ;
        RECT  90.144 267.756 90.168 267.84 ;
    END
  END out_res[285]
  PIN out_res[286]
    DIRECTION OUTPUT ;
    USE SIGNAL ;
    PORT
      LAYER M5 ;
        RECT  90.384 267.756 90.408 267.84 ;
    END
  END out_res[286]
  PIN out_res[287]
    DIRECTION OUTPUT ;
    USE SIGNAL ;
    PORT
      LAYER M5 ;
        RECT  90.624 267.756 90.648 267.84 ;
    END
  END out_res[287]
  PIN out_res[288]
    DIRECTION OUTPUT ;
    USE SIGNAL ;
    PORT
      LAYER M5 ;
        RECT  90.864 267.756 90.888 267.84 ;
    END
  END out_res[288]
  PIN out_res[289]
    DIRECTION OUTPUT ;
    USE SIGNAL ;
    PORT
      LAYER M5 ;
        RECT  91.104 267.756 91.128 267.84 ;
    END
  END out_res[289]
  PIN out_res[28]
    DIRECTION OUTPUT ;
    USE SIGNAL ;
    PORT
      LAYER M5 ;
        RECT  28.464 267.756 28.488 267.84 ;
    END
  END out_res[28]
  PIN out_res[290]
    DIRECTION OUTPUT ;
    USE SIGNAL ;
    PORT
      LAYER M5 ;
        RECT  91.344 267.756 91.368 267.84 ;
    END
  END out_res[290]
  PIN out_res[291]
    DIRECTION OUTPUT ;
    USE SIGNAL ;
    PORT
      LAYER M5 ;
        RECT  91.584 267.756 91.608 267.84 ;
    END
  END out_res[291]
  PIN out_res[292]
    DIRECTION OUTPUT ;
    USE SIGNAL ;
    PORT
      LAYER M5 ;
        RECT  91.824 267.756 91.848 267.84 ;
    END
  END out_res[292]
  PIN out_res[293]
    DIRECTION OUTPUT ;
    USE SIGNAL ;
    PORT
      LAYER M5 ;
        RECT  92.064 267.756 92.088 267.84 ;
    END
  END out_res[293]
  PIN out_res[294]
    DIRECTION OUTPUT ;
    USE SIGNAL ;
    PORT
      LAYER M5 ;
        RECT  92.304 267.756 92.328 267.84 ;
    END
  END out_res[294]
  PIN out_res[295]
    DIRECTION OUTPUT ;
    USE SIGNAL ;
    PORT
      LAYER M5 ;
        RECT  92.544 267.756 92.568 267.84 ;
    END
  END out_res[295]
  PIN out_res[296]
    DIRECTION OUTPUT ;
    USE SIGNAL ;
    PORT
      LAYER M5 ;
        RECT  92.784 267.756 92.808 267.84 ;
    END
  END out_res[296]
  PIN out_res[297]
    DIRECTION OUTPUT ;
    USE SIGNAL ;
    PORT
      LAYER M5 ;
        RECT  93.024 267.756 93.048 267.84 ;
    END
  END out_res[297]
  PIN out_res[298]
    DIRECTION OUTPUT ;
    USE SIGNAL ;
    PORT
      LAYER M5 ;
        RECT  93.264 267.756 93.288 267.84 ;
    END
  END out_res[298]
  PIN out_res[299]
    DIRECTION OUTPUT ;
    USE SIGNAL ;
    PORT
      LAYER M5 ;
        RECT  93.504 267.756 93.528 267.84 ;
    END
  END out_res[299]
  PIN out_res[29]
    DIRECTION OUTPUT ;
    USE SIGNAL ;
    PORT
      LAYER M5 ;
        RECT  28.704 267.756 28.728 267.84 ;
    END
  END out_res[29]
  PIN out_res[2]
    DIRECTION OUTPUT ;
    USE SIGNAL ;
    PORT
      LAYER M5 ;
        RECT  22.224 267.756 22.248 267.84 ;
    END
  END out_res[2]
  PIN out_res[300]
    DIRECTION OUTPUT ;
    USE SIGNAL ;
    PORT
      LAYER M5 ;
        RECT  93.744 267.756 93.768 267.84 ;
    END
  END out_res[300]
  PIN out_res[301]
    DIRECTION OUTPUT ;
    USE SIGNAL ;
    PORT
      LAYER M5 ;
        RECT  93.984 267.756 94.008 267.84 ;
    END
  END out_res[301]
  PIN out_res[302]
    DIRECTION OUTPUT ;
    USE SIGNAL ;
    PORT
      LAYER M5 ;
        RECT  94.224 267.756 94.248 267.84 ;
    END
  END out_res[302]
  PIN out_res[303]
    DIRECTION OUTPUT ;
    USE SIGNAL ;
    PORT
      LAYER M5 ;
        RECT  94.464 267.756 94.488 267.84 ;
    END
  END out_res[303]
  PIN out_res[304]
    DIRECTION OUTPUT ;
    USE SIGNAL ;
    PORT
      LAYER M5 ;
        RECT  94.704 267.756 94.728 267.84 ;
    END
  END out_res[304]
  PIN out_res[305]
    DIRECTION OUTPUT ;
    USE SIGNAL ;
    PORT
      LAYER M5 ;
        RECT  94.944 267.756 94.968 267.84 ;
    END
  END out_res[305]
  PIN out_res[306]
    DIRECTION OUTPUT ;
    USE SIGNAL ;
    PORT
      LAYER M5 ;
        RECT  95.184 267.756 95.208 267.84 ;
    END
  END out_res[306]
  PIN out_res[307]
    DIRECTION OUTPUT ;
    USE SIGNAL ;
    PORT
      LAYER M5 ;
        RECT  95.424 267.756 95.448 267.84 ;
    END
  END out_res[307]
  PIN out_res[308]
    DIRECTION OUTPUT ;
    USE SIGNAL ;
    PORT
      LAYER M5 ;
        RECT  95.664 267.756 95.688 267.84 ;
    END
  END out_res[308]
  PIN out_res[309]
    DIRECTION OUTPUT ;
    USE SIGNAL ;
    PORT
      LAYER M5 ;
        RECT  95.904 267.756 95.928 267.84 ;
    END
  END out_res[309]
  PIN out_res[30]
    DIRECTION OUTPUT ;
    USE SIGNAL ;
    PORT
      LAYER M5 ;
        RECT  28.944 267.756 28.968 267.84 ;
    END
  END out_res[30]
  PIN out_res[310]
    DIRECTION OUTPUT ;
    USE SIGNAL ;
    PORT
      LAYER M5 ;
        RECT  96.144 267.756 96.168 267.84 ;
    END
  END out_res[310]
  PIN out_res[311]
    DIRECTION OUTPUT ;
    USE SIGNAL ;
    PORT
      LAYER M5 ;
        RECT  96.384 267.756 96.408 267.84 ;
    END
  END out_res[311]
  PIN out_res[312]
    DIRECTION OUTPUT ;
    USE SIGNAL ;
    PORT
      LAYER M5 ;
        RECT  96.624 267.756 96.648 267.84 ;
    END
  END out_res[312]
  PIN out_res[313]
    DIRECTION OUTPUT ;
    USE SIGNAL ;
    PORT
      LAYER M5 ;
        RECT  96.864 267.756 96.888 267.84 ;
    END
  END out_res[313]
  PIN out_res[314]
    DIRECTION OUTPUT ;
    USE SIGNAL ;
    PORT
      LAYER M5 ;
        RECT  97.104 267.756 97.128 267.84 ;
    END
  END out_res[314]
  PIN out_res[315]
    DIRECTION OUTPUT ;
    USE SIGNAL ;
    PORT
      LAYER M5 ;
        RECT  97.344 267.756 97.368 267.84 ;
    END
  END out_res[315]
  PIN out_res[316]
    DIRECTION OUTPUT ;
    USE SIGNAL ;
    PORT
      LAYER M5 ;
        RECT  97.584 267.756 97.608 267.84 ;
    END
  END out_res[316]
  PIN out_res[317]
    DIRECTION OUTPUT ;
    USE SIGNAL ;
    PORT
      LAYER M5 ;
        RECT  97.824 267.756 97.848 267.84 ;
    END
  END out_res[317]
  PIN out_res[318]
    DIRECTION OUTPUT ;
    USE SIGNAL ;
    PORT
      LAYER M5 ;
        RECT  98.064 267.756 98.088 267.84 ;
    END
  END out_res[318]
  PIN out_res[319]
    DIRECTION OUTPUT ;
    USE SIGNAL ;
    PORT
      LAYER M5 ;
        RECT  98.304 267.756 98.328 267.84 ;
    END
  END out_res[319]
  PIN out_res[31]
    DIRECTION OUTPUT ;
    USE SIGNAL ;
    PORT
      LAYER M5 ;
        RECT  29.184 267.756 29.208 267.84 ;
    END
  END out_res[31]
  PIN out_res[320]
    DIRECTION OUTPUT ;
    USE SIGNAL ;
    PORT
      LAYER M5 ;
        RECT  98.544 267.756 98.568 267.84 ;
    END
  END out_res[320]
  PIN out_res[321]
    DIRECTION OUTPUT ;
    USE SIGNAL ;
    PORT
      LAYER M5 ;
        RECT  98.784 267.756 98.808 267.84 ;
    END
  END out_res[321]
  PIN out_res[322]
    DIRECTION OUTPUT ;
    USE SIGNAL ;
    PORT
      LAYER M5 ;
        RECT  99.024 267.756 99.048 267.84 ;
    END
  END out_res[322]
  PIN out_res[323]
    DIRECTION OUTPUT ;
    USE SIGNAL ;
    PORT
      LAYER M5 ;
        RECT  99.264 267.756 99.288 267.84 ;
    END
  END out_res[323]
  PIN out_res[324]
    DIRECTION OUTPUT ;
    USE SIGNAL ;
    PORT
      LAYER M5 ;
        RECT  99.504 267.756 99.528 267.84 ;
    END
  END out_res[324]
  PIN out_res[325]
    DIRECTION OUTPUT ;
    USE SIGNAL ;
    PORT
      LAYER M5 ;
        RECT  99.744 267.756 99.768 267.84 ;
    END
  END out_res[325]
  PIN out_res[326]
    DIRECTION OUTPUT ;
    USE SIGNAL ;
    PORT
      LAYER M5 ;
        RECT  99.984 267.756 100.008 267.84 ;
    END
  END out_res[326]
  PIN out_res[327]
    DIRECTION OUTPUT ;
    USE SIGNAL ;
    PORT
      LAYER M5 ;
        RECT  100.224 267.756 100.248 267.84 ;
    END
  END out_res[327]
  PIN out_res[328]
    DIRECTION OUTPUT ;
    USE SIGNAL ;
    PORT
      LAYER M5 ;
        RECT  100.464 267.756 100.488 267.84 ;
    END
  END out_res[328]
  PIN out_res[329]
    DIRECTION OUTPUT ;
    USE SIGNAL ;
    PORT
      LAYER M5 ;
        RECT  100.704 267.756 100.728 267.84 ;
    END
  END out_res[329]
  PIN out_res[32]
    DIRECTION OUTPUT ;
    USE SIGNAL ;
    PORT
      LAYER M5 ;
        RECT  29.424 267.756 29.448 267.84 ;
    END
  END out_res[32]
  PIN out_res[330]
    DIRECTION OUTPUT ;
    USE SIGNAL ;
    PORT
      LAYER M5 ;
        RECT  100.944 267.756 100.968 267.84 ;
    END
  END out_res[330]
  PIN out_res[331]
    DIRECTION OUTPUT ;
    USE SIGNAL ;
    PORT
      LAYER M5 ;
        RECT  101.184 267.756 101.208 267.84 ;
    END
  END out_res[331]
  PIN out_res[332]
    DIRECTION OUTPUT ;
    USE SIGNAL ;
    PORT
      LAYER M5 ;
        RECT  101.424 267.756 101.448 267.84 ;
    END
  END out_res[332]
  PIN out_res[333]
    DIRECTION OUTPUT ;
    USE SIGNAL ;
    PORT
      LAYER M5 ;
        RECT  101.664 267.756 101.688 267.84 ;
    END
  END out_res[333]
  PIN out_res[334]
    DIRECTION OUTPUT ;
    USE SIGNAL ;
    PORT
      LAYER M5 ;
        RECT  101.904 267.756 101.928 267.84 ;
    END
  END out_res[334]
  PIN out_res[335]
    DIRECTION OUTPUT ;
    USE SIGNAL ;
    PORT
      LAYER M5 ;
        RECT  102.144 267.756 102.168 267.84 ;
    END
  END out_res[335]
  PIN out_res[336]
    DIRECTION OUTPUT ;
    USE SIGNAL ;
    PORT
      LAYER M5 ;
        RECT  102.384 267.756 102.408 267.84 ;
    END
  END out_res[336]
  PIN out_res[337]
    DIRECTION OUTPUT ;
    USE SIGNAL ;
    PORT
      LAYER M5 ;
        RECT  102.624 267.756 102.648 267.84 ;
    END
  END out_res[337]
  PIN out_res[338]
    DIRECTION OUTPUT ;
    USE SIGNAL ;
    PORT
      LAYER M5 ;
        RECT  102.864 267.756 102.888 267.84 ;
    END
  END out_res[338]
  PIN out_res[339]
    DIRECTION OUTPUT ;
    USE SIGNAL ;
    PORT
      LAYER M5 ;
        RECT  103.104 267.756 103.128 267.84 ;
    END
  END out_res[339]
  PIN out_res[33]
    DIRECTION OUTPUT ;
    USE SIGNAL ;
    PORT
      LAYER M5 ;
        RECT  29.664 267.756 29.688 267.84 ;
    END
  END out_res[33]
  PIN out_res[340]
    DIRECTION OUTPUT ;
    USE SIGNAL ;
    PORT
      LAYER M5 ;
        RECT  103.344 267.756 103.368 267.84 ;
    END
  END out_res[340]
  PIN out_res[341]
    DIRECTION OUTPUT ;
    USE SIGNAL ;
    PORT
      LAYER M5 ;
        RECT  103.584 267.756 103.608 267.84 ;
    END
  END out_res[341]
  PIN out_res[342]
    DIRECTION OUTPUT ;
    USE SIGNAL ;
    PORT
      LAYER M5 ;
        RECT  103.824 267.756 103.848 267.84 ;
    END
  END out_res[342]
  PIN out_res[343]
    DIRECTION OUTPUT ;
    USE SIGNAL ;
    PORT
      LAYER M5 ;
        RECT  104.064 267.756 104.088 267.84 ;
    END
  END out_res[343]
  PIN out_res[344]
    DIRECTION OUTPUT ;
    USE SIGNAL ;
    PORT
      LAYER M5 ;
        RECT  104.304 267.756 104.328 267.84 ;
    END
  END out_res[344]
  PIN out_res[345]
    DIRECTION OUTPUT ;
    USE SIGNAL ;
    PORT
      LAYER M5 ;
        RECT  104.544 267.756 104.568 267.84 ;
    END
  END out_res[345]
  PIN out_res[346]
    DIRECTION OUTPUT ;
    USE SIGNAL ;
    PORT
      LAYER M5 ;
        RECT  104.784 267.756 104.808 267.84 ;
    END
  END out_res[346]
  PIN out_res[347]
    DIRECTION OUTPUT ;
    USE SIGNAL ;
    PORT
      LAYER M5 ;
        RECT  105.024 267.756 105.048 267.84 ;
    END
  END out_res[347]
  PIN out_res[348]
    DIRECTION OUTPUT ;
    USE SIGNAL ;
    PORT
      LAYER M5 ;
        RECT  105.264 267.756 105.288 267.84 ;
    END
  END out_res[348]
  PIN out_res[349]
    DIRECTION OUTPUT ;
    USE SIGNAL ;
    PORT
      LAYER M5 ;
        RECT  105.504 267.756 105.528 267.84 ;
    END
  END out_res[349]
  PIN out_res[34]
    DIRECTION OUTPUT ;
    USE SIGNAL ;
    PORT
      LAYER M5 ;
        RECT  29.904 267.756 29.928 267.84 ;
    END
  END out_res[34]
  PIN out_res[350]
    DIRECTION OUTPUT ;
    USE SIGNAL ;
    PORT
      LAYER M5 ;
        RECT  105.744 267.756 105.768 267.84 ;
    END
  END out_res[350]
  PIN out_res[351]
    DIRECTION OUTPUT ;
    USE SIGNAL ;
    PORT
      LAYER M5 ;
        RECT  105.984 267.756 106.008 267.84 ;
    END
  END out_res[351]
  PIN out_res[352]
    DIRECTION OUTPUT ;
    USE SIGNAL ;
    PORT
      LAYER M5 ;
        RECT  106.224 267.756 106.248 267.84 ;
    END
  END out_res[352]
  PIN out_res[353]
    DIRECTION OUTPUT ;
    USE SIGNAL ;
    PORT
      LAYER M5 ;
        RECT  106.464 267.756 106.488 267.84 ;
    END
  END out_res[353]
  PIN out_res[354]
    DIRECTION OUTPUT ;
    USE SIGNAL ;
    PORT
      LAYER M5 ;
        RECT  106.704 267.756 106.728 267.84 ;
    END
  END out_res[354]
  PIN out_res[355]
    DIRECTION OUTPUT ;
    USE SIGNAL ;
    PORT
      LAYER M5 ;
        RECT  106.944 267.756 106.968 267.84 ;
    END
  END out_res[355]
  PIN out_res[356]
    DIRECTION OUTPUT ;
    USE SIGNAL ;
    PORT
      LAYER M5 ;
        RECT  107.184 267.756 107.208 267.84 ;
    END
  END out_res[356]
  PIN out_res[357]
    DIRECTION OUTPUT ;
    USE SIGNAL ;
    PORT
      LAYER M5 ;
        RECT  107.424 267.756 107.448 267.84 ;
    END
  END out_res[357]
  PIN out_res[358]
    DIRECTION OUTPUT ;
    USE SIGNAL ;
    PORT
      LAYER M5 ;
        RECT  107.664 267.756 107.688 267.84 ;
    END
  END out_res[358]
  PIN out_res[359]
    DIRECTION OUTPUT ;
    USE SIGNAL ;
    PORT
      LAYER M5 ;
        RECT  107.904 267.756 107.928 267.84 ;
    END
  END out_res[359]
  PIN out_res[35]
    DIRECTION OUTPUT ;
    USE SIGNAL ;
    PORT
      LAYER M5 ;
        RECT  30.144 267.756 30.168 267.84 ;
    END
  END out_res[35]
  PIN out_res[360]
    DIRECTION OUTPUT ;
    USE SIGNAL ;
    PORT
      LAYER M5 ;
        RECT  108.144 267.756 108.168 267.84 ;
    END
  END out_res[360]
  PIN out_res[361]
    DIRECTION OUTPUT ;
    USE SIGNAL ;
    PORT
      LAYER M5 ;
        RECT  108.384 267.756 108.408 267.84 ;
    END
  END out_res[361]
  PIN out_res[362]
    DIRECTION OUTPUT ;
    USE SIGNAL ;
    PORT
      LAYER M5 ;
        RECT  108.624 267.756 108.648 267.84 ;
    END
  END out_res[362]
  PIN out_res[363]
    DIRECTION OUTPUT ;
    USE SIGNAL ;
    PORT
      LAYER M5 ;
        RECT  108.864 267.756 108.888 267.84 ;
    END
  END out_res[363]
  PIN out_res[364]
    DIRECTION OUTPUT ;
    USE SIGNAL ;
    PORT
      LAYER M5 ;
        RECT  109.104 267.756 109.128 267.84 ;
    END
  END out_res[364]
  PIN out_res[365]
    DIRECTION OUTPUT ;
    USE SIGNAL ;
    PORT
      LAYER M5 ;
        RECT  109.344 267.756 109.368 267.84 ;
    END
  END out_res[365]
  PIN out_res[366]
    DIRECTION OUTPUT ;
    USE SIGNAL ;
    PORT
      LAYER M5 ;
        RECT  109.584 267.756 109.608 267.84 ;
    END
  END out_res[366]
  PIN out_res[367]
    DIRECTION OUTPUT ;
    USE SIGNAL ;
    PORT
      LAYER M5 ;
        RECT  109.824 267.756 109.848 267.84 ;
    END
  END out_res[367]
  PIN out_res[368]
    DIRECTION OUTPUT ;
    USE SIGNAL ;
    PORT
      LAYER M5 ;
        RECT  110.064 267.756 110.088 267.84 ;
    END
  END out_res[368]
  PIN out_res[369]
    DIRECTION OUTPUT ;
    USE SIGNAL ;
    PORT
      LAYER M5 ;
        RECT  110.304 267.756 110.328 267.84 ;
    END
  END out_res[369]
  PIN out_res[36]
    DIRECTION OUTPUT ;
    USE SIGNAL ;
    PORT
      LAYER M5 ;
        RECT  30.384 267.756 30.408 267.84 ;
    END
  END out_res[36]
  PIN out_res[370]
    DIRECTION OUTPUT ;
    USE SIGNAL ;
    PORT
      LAYER M5 ;
        RECT  110.544 267.756 110.568 267.84 ;
    END
  END out_res[370]
  PIN out_res[371]
    DIRECTION OUTPUT ;
    USE SIGNAL ;
    PORT
      LAYER M5 ;
        RECT  110.784 267.756 110.808 267.84 ;
    END
  END out_res[371]
  PIN out_res[372]
    DIRECTION OUTPUT ;
    USE SIGNAL ;
    PORT
      LAYER M5 ;
        RECT  111.024 267.756 111.048 267.84 ;
    END
  END out_res[372]
  PIN out_res[373]
    DIRECTION OUTPUT ;
    USE SIGNAL ;
    PORT
      LAYER M5 ;
        RECT  111.264 267.756 111.288 267.84 ;
    END
  END out_res[373]
  PIN out_res[374]
    DIRECTION OUTPUT ;
    USE SIGNAL ;
    PORT
      LAYER M5 ;
        RECT  111.504 267.756 111.528 267.84 ;
    END
  END out_res[374]
  PIN out_res[375]
    DIRECTION OUTPUT ;
    USE SIGNAL ;
    PORT
      LAYER M5 ;
        RECT  111.744 267.756 111.768 267.84 ;
    END
  END out_res[375]
  PIN out_res[376]
    DIRECTION OUTPUT ;
    USE SIGNAL ;
    PORT
      LAYER M5 ;
        RECT  111.984 267.756 112.008 267.84 ;
    END
  END out_res[376]
  PIN out_res[377]
    DIRECTION OUTPUT ;
    USE SIGNAL ;
    PORT
      LAYER M5 ;
        RECT  112.224 267.756 112.248 267.84 ;
    END
  END out_res[377]
  PIN out_res[378]
    DIRECTION OUTPUT ;
    USE SIGNAL ;
    PORT
      LAYER M5 ;
        RECT  112.464 267.756 112.488 267.84 ;
    END
  END out_res[378]
  PIN out_res[379]
    DIRECTION OUTPUT ;
    USE SIGNAL ;
    PORT
      LAYER M5 ;
        RECT  112.704 267.756 112.728 267.84 ;
    END
  END out_res[379]
  PIN out_res[37]
    DIRECTION OUTPUT ;
    USE SIGNAL ;
    PORT
      LAYER M5 ;
        RECT  30.624 267.756 30.648 267.84 ;
    END
  END out_res[37]
  PIN out_res[380]
    DIRECTION OUTPUT ;
    USE SIGNAL ;
    PORT
      LAYER M5 ;
        RECT  112.944 267.756 112.968 267.84 ;
    END
  END out_res[380]
  PIN out_res[381]
    DIRECTION OUTPUT ;
    USE SIGNAL ;
    PORT
      LAYER M5 ;
        RECT  113.184 267.756 113.208 267.84 ;
    END
  END out_res[381]
  PIN out_res[382]
    DIRECTION OUTPUT ;
    USE SIGNAL ;
    PORT
      LAYER M5 ;
        RECT  113.424 267.756 113.448 267.84 ;
    END
  END out_res[382]
  PIN out_res[383]
    DIRECTION OUTPUT ;
    USE SIGNAL ;
    PORT
      LAYER M5 ;
        RECT  113.664 267.756 113.688 267.84 ;
    END
  END out_res[383]
  PIN out_res[384]
    DIRECTION OUTPUT ;
    USE SIGNAL ;
    PORT
      LAYER M5 ;
        RECT  113.904 267.756 113.928 267.84 ;
    END
  END out_res[384]
  PIN out_res[385]
    DIRECTION OUTPUT ;
    USE SIGNAL ;
    PORT
      LAYER M5 ;
        RECT  114.144 267.756 114.168 267.84 ;
    END
  END out_res[385]
  PIN out_res[386]
    DIRECTION OUTPUT ;
    USE SIGNAL ;
    PORT
      LAYER M5 ;
        RECT  114.384 267.756 114.408 267.84 ;
    END
  END out_res[386]
  PIN out_res[387]
    DIRECTION OUTPUT ;
    USE SIGNAL ;
    PORT
      LAYER M5 ;
        RECT  114.624 267.756 114.648 267.84 ;
    END
  END out_res[387]
  PIN out_res[388]
    DIRECTION OUTPUT ;
    USE SIGNAL ;
    PORT
      LAYER M5 ;
        RECT  114.864 267.756 114.888 267.84 ;
    END
  END out_res[388]
  PIN out_res[389]
    DIRECTION OUTPUT ;
    USE SIGNAL ;
    PORT
      LAYER M5 ;
        RECT  115.104 267.756 115.128 267.84 ;
    END
  END out_res[389]
  PIN out_res[38]
    DIRECTION OUTPUT ;
    USE SIGNAL ;
    PORT
      LAYER M5 ;
        RECT  30.864 267.756 30.888 267.84 ;
    END
  END out_res[38]
  PIN out_res[390]
    DIRECTION OUTPUT ;
    USE SIGNAL ;
    PORT
      LAYER M5 ;
        RECT  115.344 267.756 115.368 267.84 ;
    END
  END out_res[390]
  PIN out_res[391]
    DIRECTION OUTPUT ;
    USE SIGNAL ;
    PORT
      LAYER M5 ;
        RECT  115.584 267.756 115.608 267.84 ;
    END
  END out_res[391]
  PIN out_res[392]
    DIRECTION OUTPUT ;
    USE SIGNAL ;
    PORT
      LAYER M5 ;
        RECT  115.824 267.756 115.848 267.84 ;
    END
  END out_res[392]
  PIN out_res[393]
    DIRECTION OUTPUT ;
    USE SIGNAL ;
    PORT
      LAYER M5 ;
        RECT  116.064 267.756 116.088 267.84 ;
    END
  END out_res[393]
  PIN out_res[394]
    DIRECTION OUTPUT ;
    USE SIGNAL ;
    PORT
      LAYER M5 ;
        RECT  116.304 267.756 116.328 267.84 ;
    END
  END out_res[394]
  PIN out_res[395]
    DIRECTION OUTPUT ;
    USE SIGNAL ;
    PORT
      LAYER M5 ;
        RECT  116.544 267.756 116.568 267.84 ;
    END
  END out_res[395]
  PIN out_res[396]
    DIRECTION OUTPUT ;
    USE SIGNAL ;
    PORT
      LAYER M5 ;
        RECT  116.784 267.756 116.808 267.84 ;
    END
  END out_res[396]
  PIN out_res[397]
    DIRECTION OUTPUT ;
    USE SIGNAL ;
    PORT
      LAYER M5 ;
        RECT  117.024 267.756 117.048 267.84 ;
    END
  END out_res[397]
  PIN out_res[398]
    DIRECTION OUTPUT ;
    USE SIGNAL ;
    PORT
      LAYER M5 ;
        RECT  117.264 267.756 117.288 267.84 ;
    END
  END out_res[398]
  PIN out_res[399]
    DIRECTION OUTPUT ;
    USE SIGNAL ;
    PORT
      LAYER M5 ;
        RECT  117.504 267.756 117.528 267.84 ;
    END
  END out_res[399]
  PIN out_res[39]
    DIRECTION OUTPUT ;
    USE SIGNAL ;
    PORT
      LAYER M5 ;
        RECT  31.104 267.756 31.128 267.84 ;
    END
  END out_res[39]
  PIN out_res[3]
    DIRECTION OUTPUT ;
    USE SIGNAL ;
    PORT
      LAYER M5 ;
        RECT  22.464 267.756 22.488 267.84 ;
    END
  END out_res[3]
  PIN out_res[400]
    DIRECTION OUTPUT ;
    USE SIGNAL ;
    PORT
      LAYER M5 ;
        RECT  117.744 267.756 117.768 267.84 ;
    END
  END out_res[400]
  PIN out_res[401]
    DIRECTION OUTPUT ;
    USE SIGNAL ;
    PORT
      LAYER M5 ;
        RECT  117.984 267.756 118.008 267.84 ;
    END
  END out_res[401]
  PIN out_res[402]
    DIRECTION OUTPUT ;
    USE SIGNAL ;
    PORT
      LAYER M5 ;
        RECT  118.224 267.756 118.248 267.84 ;
    END
  END out_res[402]
  PIN out_res[403]
    DIRECTION OUTPUT ;
    USE SIGNAL ;
    PORT
      LAYER M5 ;
        RECT  118.464 267.756 118.488 267.84 ;
    END
  END out_res[403]
  PIN out_res[404]
    DIRECTION OUTPUT ;
    USE SIGNAL ;
    PORT
      LAYER M5 ;
        RECT  118.704 267.756 118.728 267.84 ;
    END
  END out_res[404]
  PIN out_res[405]
    DIRECTION OUTPUT ;
    USE SIGNAL ;
    PORT
      LAYER M5 ;
        RECT  118.944 267.756 118.968 267.84 ;
    END
  END out_res[405]
  PIN out_res[406]
    DIRECTION OUTPUT ;
    USE SIGNAL ;
    PORT
      LAYER M5 ;
        RECT  119.184 267.756 119.208 267.84 ;
    END
  END out_res[406]
  PIN out_res[407]
    DIRECTION OUTPUT ;
    USE SIGNAL ;
    PORT
      LAYER M5 ;
        RECT  119.424 267.756 119.448 267.84 ;
    END
  END out_res[407]
  PIN out_res[408]
    DIRECTION OUTPUT ;
    USE SIGNAL ;
    PORT
      LAYER M5 ;
        RECT  119.664 267.756 119.688 267.84 ;
    END
  END out_res[408]
  PIN out_res[409]
    DIRECTION OUTPUT ;
    USE SIGNAL ;
    PORT
      LAYER M5 ;
        RECT  119.904 267.756 119.928 267.84 ;
    END
  END out_res[409]
  PIN out_res[40]
    DIRECTION OUTPUT ;
    USE SIGNAL ;
    PORT
      LAYER M5 ;
        RECT  31.344 267.756 31.368 267.84 ;
    END
  END out_res[40]
  PIN out_res[410]
    DIRECTION OUTPUT ;
    USE SIGNAL ;
    PORT
      LAYER M5 ;
        RECT  120.144 267.756 120.168 267.84 ;
    END
  END out_res[410]
  PIN out_res[411]
    DIRECTION OUTPUT ;
    USE SIGNAL ;
    PORT
      LAYER M5 ;
        RECT  120.384 267.756 120.408 267.84 ;
    END
  END out_res[411]
  PIN out_res[412]
    DIRECTION OUTPUT ;
    USE SIGNAL ;
    PORT
      LAYER M5 ;
        RECT  120.624 267.756 120.648 267.84 ;
    END
  END out_res[412]
  PIN out_res[413]
    DIRECTION OUTPUT ;
    USE SIGNAL ;
    PORT
      LAYER M5 ;
        RECT  120.864 267.756 120.888 267.84 ;
    END
  END out_res[413]
  PIN out_res[414]
    DIRECTION OUTPUT ;
    USE SIGNAL ;
    PORT
      LAYER M5 ;
        RECT  121.104 267.756 121.128 267.84 ;
    END
  END out_res[414]
  PIN out_res[415]
    DIRECTION OUTPUT ;
    USE SIGNAL ;
    PORT
      LAYER M5 ;
        RECT  121.344 267.756 121.368 267.84 ;
    END
  END out_res[415]
  PIN out_res[416]
    DIRECTION OUTPUT ;
    USE SIGNAL ;
    PORT
      LAYER M5 ;
        RECT  121.584 267.756 121.608 267.84 ;
    END
  END out_res[416]
  PIN out_res[417]
    DIRECTION OUTPUT ;
    USE SIGNAL ;
    PORT
      LAYER M5 ;
        RECT  121.824 267.756 121.848 267.84 ;
    END
  END out_res[417]
  PIN out_res[418]
    DIRECTION OUTPUT ;
    USE SIGNAL ;
    PORT
      LAYER M5 ;
        RECT  122.064 267.756 122.088 267.84 ;
    END
  END out_res[418]
  PIN out_res[419]
    DIRECTION OUTPUT ;
    USE SIGNAL ;
    PORT
      LAYER M5 ;
        RECT  122.304 267.756 122.328 267.84 ;
    END
  END out_res[419]
  PIN out_res[41]
    DIRECTION OUTPUT ;
    USE SIGNAL ;
    PORT
      LAYER M5 ;
        RECT  31.584 267.756 31.608 267.84 ;
    END
  END out_res[41]
  PIN out_res[420]
    DIRECTION OUTPUT ;
    USE SIGNAL ;
    PORT
      LAYER M5 ;
        RECT  122.544 267.756 122.568 267.84 ;
    END
  END out_res[420]
  PIN out_res[421]
    DIRECTION OUTPUT ;
    USE SIGNAL ;
    PORT
      LAYER M5 ;
        RECT  122.784 267.756 122.808 267.84 ;
    END
  END out_res[421]
  PIN out_res[422]
    DIRECTION OUTPUT ;
    USE SIGNAL ;
    PORT
      LAYER M5 ;
        RECT  123.024 267.756 123.048 267.84 ;
    END
  END out_res[422]
  PIN out_res[423]
    DIRECTION OUTPUT ;
    USE SIGNAL ;
    PORT
      LAYER M5 ;
        RECT  123.264 267.756 123.288 267.84 ;
    END
  END out_res[423]
  PIN out_res[424]
    DIRECTION OUTPUT ;
    USE SIGNAL ;
    PORT
      LAYER M5 ;
        RECT  123.504 267.756 123.528 267.84 ;
    END
  END out_res[424]
  PIN out_res[425]
    DIRECTION OUTPUT ;
    USE SIGNAL ;
    PORT
      LAYER M5 ;
        RECT  123.744 267.756 123.768 267.84 ;
    END
  END out_res[425]
  PIN out_res[426]
    DIRECTION OUTPUT ;
    USE SIGNAL ;
    PORT
      LAYER M5 ;
        RECT  123.984 267.756 124.008 267.84 ;
    END
  END out_res[426]
  PIN out_res[427]
    DIRECTION OUTPUT ;
    USE SIGNAL ;
    PORT
      LAYER M5 ;
        RECT  124.224 267.756 124.248 267.84 ;
    END
  END out_res[427]
  PIN out_res[428]
    DIRECTION OUTPUT ;
    USE SIGNAL ;
    PORT
      LAYER M5 ;
        RECT  124.464 267.756 124.488 267.84 ;
    END
  END out_res[428]
  PIN out_res[429]
    DIRECTION OUTPUT ;
    USE SIGNAL ;
    PORT
      LAYER M5 ;
        RECT  124.704 267.756 124.728 267.84 ;
    END
  END out_res[429]
  PIN out_res[42]
    DIRECTION OUTPUT ;
    USE SIGNAL ;
    PORT
      LAYER M5 ;
        RECT  31.824 267.756 31.848 267.84 ;
    END
  END out_res[42]
  PIN out_res[430]
    DIRECTION OUTPUT ;
    USE SIGNAL ;
    PORT
      LAYER M5 ;
        RECT  124.944 267.756 124.968 267.84 ;
    END
  END out_res[430]
  PIN out_res[431]
    DIRECTION OUTPUT ;
    USE SIGNAL ;
    PORT
      LAYER M5 ;
        RECT  125.184 267.756 125.208 267.84 ;
    END
  END out_res[431]
  PIN out_res[432]
    DIRECTION OUTPUT ;
    USE SIGNAL ;
    PORT
      LAYER M5 ;
        RECT  125.424 267.756 125.448 267.84 ;
    END
  END out_res[432]
  PIN out_res[433]
    DIRECTION OUTPUT ;
    USE SIGNAL ;
    PORT
      LAYER M5 ;
        RECT  125.664 267.756 125.688 267.84 ;
    END
  END out_res[433]
  PIN out_res[434]
    DIRECTION OUTPUT ;
    USE SIGNAL ;
    PORT
      LAYER M5 ;
        RECT  125.904 267.756 125.928 267.84 ;
    END
  END out_res[434]
  PIN out_res[435]
    DIRECTION OUTPUT ;
    USE SIGNAL ;
    PORT
      LAYER M5 ;
        RECT  126.144 267.756 126.168 267.84 ;
    END
  END out_res[435]
  PIN out_res[436]
    DIRECTION OUTPUT ;
    USE SIGNAL ;
    PORT
      LAYER M5 ;
        RECT  126.384 267.756 126.408 267.84 ;
    END
  END out_res[436]
  PIN out_res[437]
    DIRECTION OUTPUT ;
    USE SIGNAL ;
    PORT
      LAYER M5 ;
        RECT  126.624 267.756 126.648 267.84 ;
    END
  END out_res[437]
  PIN out_res[438]
    DIRECTION OUTPUT ;
    USE SIGNAL ;
    PORT
      LAYER M5 ;
        RECT  126.864 267.756 126.888 267.84 ;
    END
  END out_res[438]
  PIN out_res[439]
    DIRECTION OUTPUT ;
    USE SIGNAL ;
    PORT
      LAYER M5 ;
        RECT  127.104 267.756 127.128 267.84 ;
    END
  END out_res[439]
  PIN out_res[43]
    DIRECTION OUTPUT ;
    USE SIGNAL ;
    PORT
      LAYER M5 ;
        RECT  32.064 267.756 32.088 267.84 ;
    END
  END out_res[43]
  PIN out_res[440]
    DIRECTION OUTPUT ;
    USE SIGNAL ;
    PORT
      LAYER M5 ;
        RECT  127.344 267.756 127.368 267.84 ;
    END
  END out_res[440]
  PIN out_res[441]
    DIRECTION OUTPUT ;
    USE SIGNAL ;
    PORT
      LAYER M5 ;
        RECT  127.584 267.756 127.608 267.84 ;
    END
  END out_res[441]
  PIN out_res[442]
    DIRECTION OUTPUT ;
    USE SIGNAL ;
    PORT
      LAYER M5 ;
        RECT  127.824 267.756 127.848 267.84 ;
    END
  END out_res[442]
  PIN out_res[443]
    DIRECTION OUTPUT ;
    USE SIGNAL ;
    PORT
      LAYER M5 ;
        RECT  128.064 267.756 128.088 267.84 ;
    END
  END out_res[443]
  PIN out_res[444]
    DIRECTION OUTPUT ;
    USE SIGNAL ;
    PORT
      LAYER M5 ;
        RECT  128.304 267.756 128.328 267.84 ;
    END
  END out_res[444]
  PIN out_res[445]
    DIRECTION OUTPUT ;
    USE SIGNAL ;
    PORT
      LAYER M5 ;
        RECT  128.544 267.756 128.568 267.84 ;
    END
  END out_res[445]
  PIN out_res[446]
    DIRECTION OUTPUT ;
    USE SIGNAL ;
    PORT
      LAYER M5 ;
        RECT  128.784 267.756 128.808 267.84 ;
    END
  END out_res[446]
  PIN out_res[447]
    DIRECTION OUTPUT ;
    USE SIGNAL ;
    PORT
      LAYER M5 ;
        RECT  129.024 267.756 129.048 267.84 ;
    END
  END out_res[447]
  PIN out_res[448]
    DIRECTION OUTPUT ;
    USE SIGNAL ;
    PORT
      LAYER M5 ;
        RECT  129.264 267.756 129.288 267.84 ;
    END
  END out_res[448]
  PIN out_res[449]
    DIRECTION OUTPUT ;
    USE SIGNAL ;
    PORT
      LAYER M5 ;
        RECT  129.504 267.756 129.528 267.84 ;
    END
  END out_res[449]
  PIN out_res[44]
    DIRECTION OUTPUT ;
    USE SIGNAL ;
    PORT
      LAYER M5 ;
        RECT  32.304 267.756 32.328 267.84 ;
    END
  END out_res[44]
  PIN out_res[450]
    DIRECTION OUTPUT ;
    USE SIGNAL ;
    PORT
      LAYER M5 ;
        RECT  129.744 267.756 129.768 267.84 ;
    END
  END out_res[450]
  PIN out_res[451]
    DIRECTION OUTPUT ;
    USE SIGNAL ;
    PORT
      LAYER M5 ;
        RECT  129.984 267.756 130.008 267.84 ;
    END
  END out_res[451]
  PIN out_res[452]
    DIRECTION OUTPUT ;
    USE SIGNAL ;
    PORT
      LAYER M5 ;
        RECT  130.224 267.756 130.248 267.84 ;
    END
  END out_res[452]
  PIN out_res[453]
    DIRECTION OUTPUT ;
    USE SIGNAL ;
    PORT
      LAYER M5 ;
        RECT  130.464 267.756 130.488 267.84 ;
    END
  END out_res[453]
  PIN out_res[454]
    DIRECTION OUTPUT ;
    USE SIGNAL ;
    PORT
      LAYER M5 ;
        RECT  130.704 267.756 130.728 267.84 ;
    END
  END out_res[454]
  PIN out_res[455]
    DIRECTION OUTPUT ;
    USE SIGNAL ;
    PORT
      LAYER M5 ;
        RECT  130.944 267.756 130.968 267.84 ;
    END
  END out_res[455]
  PIN out_res[456]
    DIRECTION OUTPUT ;
    USE SIGNAL ;
    PORT
      LAYER M5 ;
        RECT  131.184 267.756 131.208 267.84 ;
    END
  END out_res[456]
  PIN out_res[457]
    DIRECTION OUTPUT ;
    USE SIGNAL ;
    PORT
      LAYER M5 ;
        RECT  131.424 267.756 131.448 267.84 ;
    END
  END out_res[457]
  PIN out_res[458]
    DIRECTION OUTPUT ;
    USE SIGNAL ;
    PORT
      LAYER M5 ;
        RECT  131.664 267.756 131.688 267.84 ;
    END
  END out_res[458]
  PIN out_res[459]
    DIRECTION OUTPUT ;
    USE SIGNAL ;
    PORT
      LAYER M5 ;
        RECT  131.904 267.756 131.928 267.84 ;
    END
  END out_res[459]
  PIN out_res[45]
    DIRECTION OUTPUT ;
    USE SIGNAL ;
    PORT
      LAYER M5 ;
        RECT  32.544 267.756 32.568 267.84 ;
    END
  END out_res[45]
  PIN out_res[460]
    DIRECTION OUTPUT ;
    USE SIGNAL ;
    PORT
      LAYER M5 ;
        RECT  132.144 267.756 132.168 267.84 ;
    END
  END out_res[460]
  PIN out_res[461]
    DIRECTION OUTPUT ;
    USE SIGNAL ;
    PORT
      LAYER M5 ;
        RECT  132.384 267.756 132.408 267.84 ;
    END
  END out_res[461]
  PIN out_res[462]
    DIRECTION OUTPUT ;
    USE SIGNAL ;
    PORT
      LAYER M5 ;
        RECT  132.624 267.756 132.648 267.84 ;
    END
  END out_res[462]
  PIN out_res[463]
    DIRECTION OUTPUT ;
    USE SIGNAL ;
    PORT
      LAYER M5 ;
        RECT  132.864 267.756 132.888 267.84 ;
    END
  END out_res[463]
  PIN out_res[464]
    DIRECTION OUTPUT ;
    USE SIGNAL ;
    PORT
      LAYER M5 ;
        RECT  133.104 267.756 133.128 267.84 ;
    END
  END out_res[464]
  PIN out_res[465]
    DIRECTION OUTPUT ;
    USE SIGNAL ;
    PORT
      LAYER M5 ;
        RECT  133.344 267.756 133.368 267.84 ;
    END
  END out_res[465]
  PIN out_res[466]
    DIRECTION OUTPUT ;
    USE SIGNAL ;
    PORT
      LAYER M5 ;
        RECT  133.584 267.756 133.608 267.84 ;
    END
  END out_res[466]
  PIN out_res[467]
    DIRECTION OUTPUT ;
    USE SIGNAL ;
    PORT
      LAYER M5 ;
        RECT  133.824 267.756 133.848 267.84 ;
    END
  END out_res[467]
  PIN out_res[468]
    DIRECTION OUTPUT ;
    USE SIGNAL ;
    PORT
      LAYER M5 ;
        RECT  134.064 267.756 134.088 267.84 ;
    END
  END out_res[468]
  PIN out_res[469]
    DIRECTION OUTPUT ;
    USE SIGNAL ;
    PORT
      LAYER M5 ;
        RECT  134.304 267.756 134.328 267.84 ;
    END
  END out_res[469]
  PIN out_res[46]
    DIRECTION OUTPUT ;
    USE SIGNAL ;
    PORT
      LAYER M5 ;
        RECT  32.784 267.756 32.808 267.84 ;
    END
  END out_res[46]
  PIN out_res[470]
    DIRECTION OUTPUT ;
    USE SIGNAL ;
    PORT
      LAYER M5 ;
        RECT  134.544 267.756 134.568 267.84 ;
    END
  END out_res[470]
  PIN out_res[471]
    DIRECTION OUTPUT ;
    USE SIGNAL ;
    PORT
      LAYER M5 ;
        RECT  134.784 267.756 134.808 267.84 ;
    END
  END out_res[471]
  PIN out_res[472]
    DIRECTION OUTPUT ;
    USE SIGNAL ;
    PORT
      LAYER M5 ;
        RECT  135.024 267.756 135.048 267.84 ;
    END
  END out_res[472]
  PIN out_res[473]
    DIRECTION OUTPUT ;
    USE SIGNAL ;
    PORT
      LAYER M5 ;
        RECT  135.264 267.756 135.288 267.84 ;
    END
  END out_res[473]
  PIN out_res[474]
    DIRECTION OUTPUT ;
    USE SIGNAL ;
    PORT
      LAYER M5 ;
        RECT  135.504 267.756 135.528 267.84 ;
    END
  END out_res[474]
  PIN out_res[475]
    DIRECTION OUTPUT ;
    USE SIGNAL ;
    PORT
      LAYER M5 ;
        RECT  135.744 267.756 135.768 267.84 ;
    END
  END out_res[475]
  PIN out_res[476]
    DIRECTION OUTPUT ;
    USE SIGNAL ;
    PORT
      LAYER M5 ;
        RECT  135.984 267.756 136.008 267.84 ;
    END
  END out_res[476]
  PIN out_res[477]
    DIRECTION OUTPUT ;
    USE SIGNAL ;
    PORT
      LAYER M5 ;
        RECT  136.224 267.756 136.248 267.84 ;
    END
  END out_res[477]
  PIN out_res[478]
    DIRECTION OUTPUT ;
    USE SIGNAL ;
    PORT
      LAYER M5 ;
        RECT  136.464 267.756 136.488 267.84 ;
    END
  END out_res[478]
  PIN out_res[479]
    DIRECTION OUTPUT ;
    USE SIGNAL ;
    PORT
      LAYER M5 ;
        RECT  136.704 267.756 136.728 267.84 ;
    END
  END out_res[479]
  PIN out_res[47]
    DIRECTION OUTPUT ;
    USE SIGNAL ;
    PORT
      LAYER M5 ;
        RECT  33.024 267.756 33.048 267.84 ;
    END
  END out_res[47]
  PIN out_res[480]
    DIRECTION OUTPUT ;
    USE SIGNAL ;
    PORT
      LAYER M5 ;
        RECT  136.944 267.756 136.968 267.84 ;
    END
  END out_res[480]
  PIN out_res[481]
    DIRECTION OUTPUT ;
    USE SIGNAL ;
    PORT
      LAYER M5 ;
        RECT  137.184 267.756 137.208 267.84 ;
    END
  END out_res[481]
  PIN out_res[482]
    DIRECTION OUTPUT ;
    USE SIGNAL ;
    PORT
      LAYER M5 ;
        RECT  137.424 267.756 137.448 267.84 ;
    END
  END out_res[482]
  PIN out_res[483]
    DIRECTION OUTPUT ;
    USE SIGNAL ;
    PORT
      LAYER M5 ;
        RECT  137.664 267.756 137.688 267.84 ;
    END
  END out_res[483]
  PIN out_res[484]
    DIRECTION OUTPUT ;
    USE SIGNAL ;
    PORT
      LAYER M5 ;
        RECT  137.904 267.756 137.928 267.84 ;
    END
  END out_res[484]
  PIN out_res[485]
    DIRECTION OUTPUT ;
    USE SIGNAL ;
    PORT
      LAYER M5 ;
        RECT  138.144 267.756 138.168 267.84 ;
    END
  END out_res[485]
  PIN out_res[486]
    DIRECTION OUTPUT ;
    USE SIGNAL ;
    PORT
      LAYER M5 ;
        RECT  138.384 267.756 138.408 267.84 ;
    END
  END out_res[486]
  PIN out_res[487]
    DIRECTION OUTPUT ;
    USE SIGNAL ;
    PORT
      LAYER M5 ;
        RECT  138.624 267.756 138.648 267.84 ;
    END
  END out_res[487]
  PIN out_res[488]
    DIRECTION OUTPUT ;
    USE SIGNAL ;
    PORT
      LAYER M5 ;
        RECT  138.864 267.756 138.888 267.84 ;
    END
  END out_res[488]
  PIN out_res[489]
    DIRECTION OUTPUT ;
    USE SIGNAL ;
    PORT
      LAYER M5 ;
        RECT  139.104 267.756 139.128 267.84 ;
    END
  END out_res[489]
  PIN out_res[48]
    DIRECTION OUTPUT ;
    USE SIGNAL ;
    PORT
      LAYER M5 ;
        RECT  33.264 267.756 33.288 267.84 ;
    END
  END out_res[48]
  PIN out_res[490]
    DIRECTION OUTPUT ;
    USE SIGNAL ;
    PORT
      LAYER M5 ;
        RECT  139.344 267.756 139.368 267.84 ;
    END
  END out_res[490]
  PIN out_res[491]
    DIRECTION OUTPUT ;
    USE SIGNAL ;
    PORT
      LAYER M5 ;
        RECT  139.584 267.756 139.608 267.84 ;
    END
  END out_res[491]
  PIN out_res[492]
    DIRECTION OUTPUT ;
    USE SIGNAL ;
    PORT
      LAYER M5 ;
        RECT  139.824 267.756 139.848 267.84 ;
    END
  END out_res[492]
  PIN out_res[493]
    DIRECTION OUTPUT ;
    USE SIGNAL ;
    PORT
      LAYER M5 ;
        RECT  140.064 267.756 140.088 267.84 ;
    END
  END out_res[493]
  PIN out_res[494]
    DIRECTION OUTPUT ;
    USE SIGNAL ;
    PORT
      LAYER M5 ;
        RECT  140.304 267.756 140.328 267.84 ;
    END
  END out_res[494]
  PIN out_res[495]
    DIRECTION OUTPUT ;
    USE SIGNAL ;
    PORT
      LAYER M5 ;
        RECT  140.544 267.756 140.568 267.84 ;
    END
  END out_res[495]
  PIN out_res[496]
    DIRECTION OUTPUT ;
    USE SIGNAL ;
    PORT
      LAYER M5 ;
        RECT  140.784 267.756 140.808 267.84 ;
    END
  END out_res[496]
  PIN out_res[497]
    DIRECTION OUTPUT ;
    USE SIGNAL ;
    PORT
      LAYER M5 ;
        RECT  141.024 267.756 141.048 267.84 ;
    END
  END out_res[497]
  PIN out_res[498]
    DIRECTION OUTPUT ;
    USE SIGNAL ;
    PORT
      LAYER M5 ;
        RECT  141.264 267.756 141.288 267.84 ;
    END
  END out_res[498]
  PIN out_res[499]
    DIRECTION OUTPUT ;
    USE SIGNAL ;
    PORT
      LAYER M5 ;
        RECT  141.504 267.756 141.528 267.84 ;
    END
  END out_res[499]
  PIN out_res[49]
    DIRECTION OUTPUT ;
    USE SIGNAL ;
    PORT
      LAYER M5 ;
        RECT  33.504 267.756 33.528 267.84 ;
    END
  END out_res[49]
  PIN out_res[4]
    DIRECTION OUTPUT ;
    USE SIGNAL ;
    PORT
      LAYER M5 ;
        RECT  22.704 267.756 22.728 267.84 ;
    END
  END out_res[4]
  PIN out_res[500]
    DIRECTION OUTPUT ;
    USE SIGNAL ;
    PORT
      LAYER M5 ;
        RECT  141.744 267.756 141.768 267.84 ;
    END
  END out_res[500]
  PIN out_res[501]
    DIRECTION OUTPUT ;
    USE SIGNAL ;
    PORT
      LAYER M5 ;
        RECT  141.984 267.756 142.008 267.84 ;
    END
  END out_res[501]
  PIN out_res[502]
    DIRECTION OUTPUT ;
    USE SIGNAL ;
    PORT
      LAYER M5 ;
        RECT  142.224 267.756 142.248 267.84 ;
    END
  END out_res[502]
  PIN out_res[503]
    DIRECTION OUTPUT ;
    USE SIGNAL ;
    PORT
      LAYER M5 ;
        RECT  142.464 267.756 142.488 267.84 ;
    END
  END out_res[503]
  PIN out_res[504]
    DIRECTION OUTPUT ;
    USE SIGNAL ;
    PORT
      LAYER M5 ;
        RECT  142.704 267.756 142.728 267.84 ;
    END
  END out_res[504]
  PIN out_res[505]
    DIRECTION OUTPUT ;
    USE SIGNAL ;
    PORT
      LAYER M5 ;
        RECT  142.944 267.756 142.968 267.84 ;
    END
  END out_res[505]
  PIN out_res[506]
    DIRECTION OUTPUT ;
    USE SIGNAL ;
    PORT
      LAYER M5 ;
        RECT  143.184 267.756 143.208 267.84 ;
    END
  END out_res[506]
  PIN out_res[507]
    DIRECTION OUTPUT ;
    USE SIGNAL ;
    PORT
      LAYER M5 ;
        RECT  143.424 267.756 143.448 267.84 ;
    END
  END out_res[507]
  PIN out_res[508]
    DIRECTION OUTPUT ;
    USE SIGNAL ;
    PORT
      LAYER M5 ;
        RECT  143.664 267.756 143.688 267.84 ;
    END
  END out_res[508]
  PIN out_res[509]
    DIRECTION OUTPUT ;
    USE SIGNAL ;
    PORT
      LAYER M5 ;
        RECT  143.904 267.756 143.928 267.84 ;
    END
  END out_res[509]
  PIN out_res[50]
    DIRECTION OUTPUT ;
    USE SIGNAL ;
    PORT
      LAYER M5 ;
        RECT  33.744 267.756 33.768 267.84 ;
    END
  END out_res[50]
  PIN out_res[510]
    DIRECTION OUTPUT ;
    USE SIGNAL ;
    PORT
      LAYER M5 ;
        RECT  144.144 267.756 144.168 267.84 ;
    END
  END out_res[510]
  PIN out_res[511]
    DIRECTION OUTPUT ;
    USE SIGNAL ;
    PORT
      LAYER M5 ;
        RECT  144.384 267.756 144.408 267.84 ;
    END
  END out_res[511]
  PIN out_res[512]
    DIRECTION OUTPUT ;
    USE SIGNAL ;
    PORT
      LAYER M5 ;
        RECT  144.624 267.756 144.648 267.84 ;
    END
  END out_res[512]
  PIN out_res[513]
    DIRECTION OUTPUT ;
    USE SIGNAL ;
    PORT
      LAYER M5 ;
        RECT  144.864 267.756 144.888 267.84 ;
    END
  END out_res[513]
  PIN out_res[514]
    DIRECTION OUTPUT ;
    USE SIGNAL ;
    PORT
      LAYER M5 ;
        RECT  145.104 267.756 145.128 267.84 ;
    END
  END out_res[514]
  PIN out_res[515]
    DIRECTION OUTPUT ;
    USE SIGNAL ;
    PORT
      LAYER M5 ;
        RECT  145.344 267.756 145.368 267.84 ;
    END
  END out_res[515]
  PIN out_res[516]
    DIRECTION OUTPUT ;
    USE SIGNAL ;
    PORT
      LAYER M5 ;
        RECT  145.584 267.756 145.608 267.84 ;
    END
  END out_res[516]
  PIN out_res[517]
    DIRECTION OUTPUT ;
    USE SIGNAL ;
    PORT
      LAYER M5 ;
        RECT  145.824 267.756 145.848 267.84 ;
    END
  END out_res[517]
  PIN out_res[518]
    DIRECTION OUTPUT ;
    USE SIGNAL ;
    PORT
      LAYER M5 ;
        RECT  146.064 267.756 146.088 267.84 ;
    END
  END out_res[518]
  PIN out_res[519]
    DIRECTION OUTPUT ;
    USE SIGNAL ;
    PORT
      LAYER M5 ;
        RECT  146.304 267.756 146.328 267.84 ;
    END
  END out_res[519]
  PIN out_res[51]
    DIRECTION OUTPUT ;
    USE SIGNAL ;
    PORT
      LAYER M5 ;
        RECT  33.984 267.756 34.008 267.84 ;
    END
  END out_res[51]
  PIN out_res[520]
    DIRECTION OUTPUT ;
    USE SIGNAL ;
    PORT
      LAYER M5 ;
        RECT  146.544 267.756 146.568 267.84 ;
    END
  END out_res[520]
  PIN out_res[521]
    DIRECTION OUTPUT ;
    USE SIGNAL ;
    PORT
      LAYER M5 ;
        RECT  146.784 267.756 146.808 267.84 ;
    END
  END out_res[521]
  PIN out_res[522]
    DIRECTION OUTPUT ;
    USE SIGNAL ;
    PORT
      LAYER M5 ;
        RECT  147.024 267.756 147.048 267.84 ;
    END
  END out_res[522]
  PIN out_res[523]
    DIRECTION OUTPUT ;
    USE SIGNAL ;
    PORT
      LAYER M5 ;
        RECT  147.264 267.756 147.288 267.84 ;
    END
  END out_res[523]
  PIN out_res[524]
    DIRECTION OUTPUT ;
    USE SIGNAL ;
    PORT
      LAYER M5 ;
        RECT  147.504 267.756 147.528 267.84 ;
    END
  END out_res[524]
  PIN out_res[525]
    DIRECTION OUTPUT ;
    USE SIGNAL ;
    PORT
      LAYER M5 ;
        RECT  147.744 267.756 147.768 267.84 ;
    END
  END out_res[525]
  PIN out_res[526]
    DIRECTION OUTPUT ;
    USE SIGNAL ;
    PORT
      LAYER M5 ;
        RECT  147.984 267.756 148.008 267.84 ;
    END
  END out_res[526]
  PIN out_res[527]
    DIRECTION OUTPUT ;
    USE SIGNAL ;
    PORT
      LAYER M5 ;
        RECT  148.224 267.756 148.248 267.84 ;
    END
  END out_res[527]
  PIN out_res[528]
    DIRECTION OUTPUT ;
    USE SIGNAL ;
    PORT
      LAYER M5 ;
        RECT  148.464 267.756 148.488 267.84 ;
    END
  END out_res[528]
  PIN out_res[529]
    DIRECTION OUTPUT ;
    USE SIGNAL ;
    PORT
      LAYER M5 ;
        RECT  148.704 267.756 148.728 267.84 ;
    END
  END out_res[529]
  PIN out_res[52]
    DIRECTION OUTPUT ;
    USE SIGNAL ;
    PORT
      LAYER M5 ;
        RECT  34.224 267.756 34.248 267.84 ;
    END
  END out_res[52]
  PIN out_res[530]
    DIRECTION OUTPUT ;
    USE SIGNAL ;
    PORT
      LAYER M5 ;
        RECT  148.944 267.756 148.968 267.84 ;
    END
  END out_res[530]
  PIN out_res[531]
    DIRECTION OUTPUT ;
    USE SIGNAL ;
    PORT
      LAYER M5 ;
        RECT  149.184 267.756 149.208 267.84 ;
    END
  END out_res[531]
  PIN out_res[532]
    DIRECTION OUTPUT ;
    USE SIGNAL ;
    PORT
      LAYER M5 ;
        RECT  149.424 267.756 149.448 267.84 ;
    END
  END out_res[532]
  PIN out_res[533]
    DIRECTION OUTPUT ;
    USE SIGNAL ;
    PORT
      LAYER M5 ;
        RECT  149.664 267.756 149.688 267.84 ;
    END
  END out_res[533]
  PIN out_res[534]
    DIRECTION OUTPUT ;
    USE SIGNAL ;
    PORT
      LAYER M5 ;
        RECT  149.904 267.756 149.928 267.84 ;
    END
  END out_res[534]
  PIN out_res[535]
    DIRECTION OUTPUT ;
    USE SIGNAL ;
    PORT
      LAYER M5 ;
        RECT  150.144 267.756 150.168 267.84 ;
    END
  END out_res[535]
  PIN out_res[536]
    DIRECTION OUTPUT ;
    USE SIGNAL ;
    PORT
      LAYER M5 ;
        RECT  150.384 267.756 150.408 267.84 ;
    END
  END out_res[536]
  PIN out_res[537]
    DIRECTION OUTPUT ;
    USE SIGNAL ;
    PORT
      LAYER M5 ;
        RECT  150.624 267.756 150.648 267.84 ;
    END
  END out_res[537]
  PIN out_res[538]
    DIRECTION OUTPUT ;
    USE SIGNAL ;
    PORT
      LAYER M5 ;
        RECT  150.864 267.756 150.888 267.84 ;
    END
  END out_res[538]
  PIN out_res[539]
    DIRECTION OUTPUT ;
    USE SIGNAL ;
    PORT
      LAYER M5 ;
        RECT  151.104 267.756 151.128 267.84 ;
    END
  END out_res[539]
  PIN out_res[53]
    DIRECTION OUTPUT ;
    USE SIGNAL ;
    PORT
      LAYER M5 ;
        RECT  34.464 267.756 34.488 267.84 ;
    END
  END out_res[53]
  PIN out_res[540]
    DIRECTION OUTPUT ;
    USE SIGNAL ;
    PORT
      LAYER M5 ;
        RECT  151.344 267.756 151.368 267.84 ;
    END
  END out_res[540]
  PIN out_res[541]
    DIRECTION OUTPUT ;
    USE SIGNAL ;
    PORT
      LAYER M5 ;
        RECT  151.584 267.756 151.608 267.84 ;
    END
  END out_res[541]
  PIN out_res[542]
    DIRECTION OUTPUT ;
    USE SIGNAL ;
    PORT
      LAYER M5 ;
        RECT  151.824 267.756 151.848 267.84 ;
    END
  END out_res[542]
  PIN out_res[543]
    DIRECTION OUTPUT ;
    USE SIGNAL ;
    PORT
      LAYER M5 ;
        RECT  152.064 267.756 152.088 267.84 ;
    END
  END out_res[543]
  PIN out_res[544]
    DIRECTION OUTPUT ;
    USE SIGNAL ;
    PORT
      LAYER M5 ;
        RECT  152.304 267.756 152.328 267.84 ;
    END
  END out_res[544]
  PIN out_res[545]
    DIRECTION OUTPUT ;
    USE SIGNAL ;
    PORT
      LAYER M5 ;
        RECT  152.544 267.756 152.568 267.84 ;
    END
  END out_res[545]
  PIN out_res[546]
    DIRECTION OUTPUT ;
    USE SIGNAL ;
    PORT
      LAYER M5 ;
        RECT  152.784 267.756 152.808 267.84 ;
    END
  END out_res[546]
  PIN out_res[547]
    DIRECTION OUTPUT ;
    USE SIGNAL ;
    PORT
      LAYER M5 ;
        RECT  153.024 267.756 153.048 267.84 ;
    END
  END out_res[547]
  PIN out_res[548]
    DIRECTION OUTPUT ;
    USE SIGNAL ;
    PORT
      LAYER M5 ;
        RECT  153.264 267.756 153.288 267.84 ;
    END
  END out_res[548]
  PIN out_res[549]
    DIRECTION OUTPUT ;
    USE SIGNAL ;
    PORT
      LAYER M5 ;
        RECT  153.504 267.756 153.528 267.84 ;
    END
  END out_res[549]
  PIN out_res[54]
    DIRECTION OUTPUT ;
    USE SIGNAL ;
    PORT
      LAYER M5 ;
        RECT  34.704 267.756 34.728 267.84 ;
    END
  END out_res[54]
  PIN out_res[550]
    DIRECTION OUTPUT ;
    USE SIGNAL ;
    PORT
      LAYER M5 ;
        RECT  153.744 267.756 153.768 267.84 ;
    END
  END out_res[550]
  PIN out_res[551]
    DIRECTION OUTPUT ;
    USE SIGNAL ;
    PORT
      LAYER M5 ;
        RECT  153.984 267.756 154.008 267.84 ;
    END
  END out_res[551]
  PIN out_res[552]
    DIRECTION OUTPUT ;
    USE SIGNAL ;
    PORT
      LAYER M5 ;
        RECT  154.224 267.756 154.248 267.84 ;
    END
  END out_res[552]
  PIN out_res[553]
    DIRECTION OUTPUT ;
    USE SIGNAL ;
    PORT
      LAYER M5 ;
        RECT  154.464 267.756 154.488 267.84 ;
    END
  END out_res[553]
  PIN out_res[554]
    DIRECTION OUTPUT ;
    USE SIGNAL ;
    PORT
      LAYER M5 ;
        RECT  154.704 267.756 154.728 267.84 ;
    END
  END out_res[554]
  PIN out_res[555]
    DIRECTION OUTPUT ;
    USE SIGNAL ;
    PORT
      LAYER M5 ;
        RECT  154.944 267.756 154.968 267.84 ;
    END
  END out_res[555]
  PIN out_res[556]
    DIRECTION OUTPUT ;
    USE SIGNAL ;
    PORT
      LAYER M5 ;
        RECT  155.184 267.756 155.208 267.84 ;
    END
  END out_res[556]
  PIN out_res[557]
    DIRECTION OUTPUT ;
    USE SIGNAL ;
    PORT
      LAYER M5 ;
        RECT  155.424 267.756 155.448 267.84 ;
    END
  END out_res[557]
  PIN out_res[558]
    DIRECTION OUTPUT ;
    USE SIGNAL ;
    PORT
      LAYER M5 ;
        RECT  155.664 267.756 155.688 267.84 ;
    END
  END out_res[558]
  PIN out_res[559]
    DIRECTION OUTPUT ;
    USE SIGNAL ;
    PORT
      LAYER M5 ;
        RECT  155.904 267.756 155.928 267.84 ;
    END
  END out_res[559]
  PIN out_res[55]
    DIRECTION OUTPUT ;
    USE SIGNAL ;
    PORT
      LAYER M5 ;
        RECT  34.944 267.756 34.968 267.84 ;
    END
  END out_res[55]
  PIN out_res[560]
    DIRECTION OUTPUT ;
    USE SIGNAL ;
    PORT
      LAYER M5 ;
        RECT  156.144 267.756 156.168 267.84 ;
    END
  END out_res[560]
  PIN out_res[561]
    DIRECTION OUTPUT ;
    USE SIGNAL ;
    PORT
      LAYER M5 ;
        RECT  156.384 267.756 156.408 267.84 ;
    END
  END out_res[561]
  PIN out_res[562]
    DIRECTION OUTPUT ;
    USE SIGNAL ;
    PORT
      LAYER M5 ;
        RECT  156.624 267.756 156.648 267.84 ;
    END
  END out_res[562]
  PIN out_res[563]
    DIRECTION OUTPUT ;
    USE SIGNAL ;
    PORT
      LAYER M5 ;
        RECT  156.864 267.756 156.888 267.84 ;
    END
  END out_res[563]
  PIN out_res[564]
    DIRECTION OUTPUT ;
    USE SIGNAL ;
    PORT
      LAYER M5 ;
        RECT  157.104 267.756 157.128 267.84 ;
    END
  END out_res[564]
  PIN out_res[565]
    DIRECTION OUTPUT ;
    USE SIGNAL ;
    PORT
      LAYER M5 ;
        RECT  157.344 267.756 157.368 267.84 ;
    END
  END out_res[565]
  PIN out_res[566]
    DIRECTION OUTPUT ;
    USE SIGNAL ;
    PORT
      LAYER M5 ;
        RECT  157.584 267.756 157.608 267.84 ;
    END
  END out_res[566]
  PIN out_res[567]
    DIRECTION OUTPUT ;
    USE SIGNAL ;
    PORT
      LAYER M5 ;
        RECT  157.824 267.756 157.848 267.84 ;
    END
  END out_res[567]
  PIN out_res[568]
    DIRECTION OUTPUT ;
    USE SIGNAL ;
    PORT
      LAYER M5 ;
        RECT  158.064 267.756 158.088 267.84 ;
    END
  END out_res[568]
  PIN out_res[569]
    DIRECTION OUTPUT ;
    USE SIGNAL ;
    PORT
      LAYER M5 ;
        RECT  158.304 267.756 158.328 267.84 ;
    END
  END out_res[569]
  PIN out_res[56]
    DIRECTION OUTPUT ;
    USE SIGNAL ;
    PORT
      LAYER M5 ;
        RECT  35.184 267.756 35.208 267.84 ;
    END
  END out_res[56]
  PIN out_res[570]
    DIRECTION OUTPUT ;
    USE SIGNAL ;
    PORT
      LAYER M5 ;
        RECT  158.544 267.756 158.568 267.84 ;
    END
  END out_res[570]
  PIN out_res[571]
    DIRECTION OUTPUT ;
    USE SIGNAL ;
    PORT
      LAYER M5 ;
        RECT  158.784 267.756 158.808 267.84 ;
    END
  END out_res[571]
  PIN out_res[572]
    DIRECTION OUTPUT ;
    USE SIGNAL ;
    PORT
      LAYER M5 ;
        RECT  159.024 267.756 159.048 267.84 ;
    END
  END out_res[572]
  PIN out_res[573]
    DIRECTION OUTPUT ;
    USE SIGNAL ;
    PORT
      LAYER M5 ;
        RECT  159.264 267.756 159.288 267.84 ;
    END
  END out_res[573]
  PIN out_res[574]
    DIRECTION OUTPUT ;
    USE SIGNAL ;
    PORT
      LAYER M5 ;
        RECT  159.504 267.756 159.528 267.84 ;
    END
  END out_res[574]
  PIN out_res[575]
    DIRECTION OUTPUT ;
    USE SIGNAL ;
    PORT
      LAYER M5 ;
        RECT  159.744 267.756 159.768 267.84 ;
    END
  END out_res[575]
  PIN out_res[57]
    DIRECTION OUTPUT ;
    USE SIGNAL ;
    PORT
      LAYER M5 ;
        RECT  35.424 267.756 35.448 267.84 ;
    END
  END out_res[57]
  PIN out_res[58]
    DIRECTION OUTPUT ;
    USE SIGNAL ;
    PORT
      LAYER M5 ;
        RECT  35.664 267.756 35.688 267.84 ;
    END
  END out_res[58]
  PIN out_res[59]
    DIRECTION OUTPUT ;
    USE SIGNAL ;
    PORT
      LAYER M5 ;
        RECT  35.904 267.756 35.928 267.84 ;
    END
  END out_res[59]
  PIN out_res[5]
    DIRECTION OUTPUT ;
    USE SIGNAL ;
    PORT
      LAYER M5 ;
        RECT  22.944 267.756 22.968 267.84 ;
    END
  END out_res[5]
  PIN out_res[60]
    DIRECTION OUTPUT ;
    USE SIGNAL ;
    PORT
      LAYER M5 ;
        RECT  36.144 267.756 36.168 267.84 ;
    END
  END out_res[60]
  PIN out_res[61]
    DIRECTION OUTPUT ;
    USE SIGNAL ;
    PORT
      LAYER M5 ;
        RECT  36.384 267.756 36.408 267.84 ;
    END
  END out_res[61]
  PIN out_res[62]
    DIRECTION OUTPUT ;
    USE SIGNAL ;
    PORT
      LAYER M5 ;
        RECT  36.624 267.756 36.648 267.84 ;
    END
  END out_res[62]
  PIN out_res[63]
    DIRECTION OUTPUT ;
    USE SIGNAL ;
    PORT
      LAYER M5 ;
        RECT  36.864 267.756 36.888 267.84 ;
    END
  END out_res[63]
  PIN out_res[64]
    DIRECTION OUTPUT ;
    USE SIGNAL ;
    PORT
      LAYER M5 ;
        RECT  37.104 267.756 37.128 267.84 ;
    END
  END out_res[64]
  PIN out_res[65]
    DIRECTION OUTPUT ;
    USE SIGNAL ;
    PORT
      LAYER M5 ;
        RECT  37.344 267.756 37.368 267.84 ;
    END
  END out_res[65]
  PIN out_res[66]
    DIRECTION OUTPUT ;
    USE SIGNAL ;
    PORT
      LAYER M5 ;
        RECT  37.584 267.756 37.608 267.84 ;
    END
  END out_res[66]
  PIN out_res[67]
    DIRECTION OUTPUT ;
    USE SIGNAL ;
    PORT
      LAYER M5 ;
        RECT  37.824 267.756 37.848 267.84 ;
    END
  END out_res[67]
  PIN out_res[68]
    DIRECTION OUTPUT ;
    USE SIGNAL ;
    PORT
      LAYER M5 ;
        RECT  38.064 267.756 38.088 267.84 ;
    END
  END out_res[68]
  PIN out_res[69]
    DIRECTION OUTPUT ;
    USE SIGNAL ;
    PORT
      LAYER M5 ;
        RECT  38.304 267.756 38.328 267.84 ;
    END
  END out_res[69]
  PIN out_res[6]
    DIRECTION OUTPUT ;
    USE SIGNAL ;
    PORT
      LAYER M5 ;
        RECT  23.184 267.756 23.208 267.84 ;
    END
  END out_res[6]
  PIN out_res[70]
    DIRECTION OUTPUT ;
    USE SIGNAL ;
    PORT
      LAYER M5 ;
        RECT  38.544 267.756 38.568 267.84 ;
    END
  END out_res[70]
  PIN out_res[71]
    DIRECTION OUTPUT ;
    USE SIGNAL ;
    PORT
      LAYER M5 ;
        RECT  38.784 267.756 38.808 267.84 ;
    END
  END out_res[71]
  PIN out_res[72]
    DIRECTION OUTPUT ;
    USE SIGNAL ;
    PORT
      LAYER M5 ;
        RECT  39.024 267.756 39.048 267.84 ;
    END
  END out_res[72]
  PIN out_res[73]
    DIRECTION OUTPUT ;
    USE SIGNAL ;
    PORT
      LAYER M5 ;
        RECT  39.264 267.756 39.288 267.84 ;
    END
  END out_res[73]
  PIN out_res[74]
    DIRECTION OUTPUT ;
    USE SIGNAL ;
    PORT
      LAYER M5 ;
        RECT  39.504 267.756 39.528 267.84 ;
    END
  END out_res[74]
  PIN out_res[75]
    DIRECTION OUTPUT ;
    USE SIGNAL ;
    PORT
      LAYER M5 ;
        RECT  39.744 267.756 39.768 267.84 ;
    END
  END out_res[75]
  PIN out_res[76]
    DIRECTION OUTPUT ;
    USE SIGNAL ;
    PORT
      LAYER M5 ;
        RECT  39.984 267.756 40.008 267.84 ;
    END
  END out_res[76]
  PIN out_res[77]
    DIRECTION OUTPUT ;
    USE SIGNAL ;
    PORT
      LAYER M5 ;
        RECT  40.224 267.756 40.248 267.84 ;
    END
  END out_res[77]
  PIN out_res[78]
    DIRECTION OUTPUT ;
    USE SIGNAL ;
    PORT
      LAYER M5 ;
        RECT  40.464 267.756 40.488 267.84 ;
    END
  END out_res[78]
  PIN out_res[79]
    DIRECTION OUTPUT ;
    USE SIGNAL ;
    PORT
      LAYER M5 ;
        RECT  40.704 267.756 40.728 267.84 ;
    END
  END out_res[79]
  PIN out_res[7]
    DIRECTION OUTPUT ;
    USE SIGNAL ;
    PORT
      LAYER M5 ;
        RECT  23.424 267.756 23.448 267.84 ;
    END
  END out_res[7]
  PIN out_res[80]
    DIRECTION OUTPUT ;
    USE SIGNAL ;
    PORT
      LAYER M5 ;
        RECT  40.944 267.756 40.968 267.84 ;
    END
  END out_res[80]
  PIN out_res[81]
    DIRECTION OUTPUT ;
    USE SIGNAL ;
    PORT
      LAYER M5 ;
        RECT  41.184 267.756 41.208 267.84 ;
    END
  END out_res[81]
  PIN out_res[82]
    DIRECTION OUTPUT ;
    USE SIGNAL ;
    PORT
      LAYER M5 ;
        RECT  41.424 267.756 41.448 267.84 ;
    END
  END out_res[82]
  PIN out_res[83]
    DIRECTION OUTPUT ;
    USE SIGNAL ;
    PORT
      LAYER M5 ;
        RECT  41.664 267.756 41.688 267.84 ;
    END
  END out_res[83]
  PIN out_res[84]
    DIRECTION OUTPUT ;
    USE SIGNAL ;
    PORT
      LAYER M5 ;
        RECT  41.904 267.756 41.928 267.84 ;
    END
  END out_res[84]
  PIN out_res[85]
    DIRECTION OUTPUT ;
    USE SIGNAL ;
    PORT
      LAYER M5 ;
        RECT  42.144 267.756 42.168 267.84 ;
    END
  END out_res[85]
  PIN out_res[86]
    DIRECTION OUTPUT ;
    USE SIGNAL ;
    PORT
      LAYER M5 ;
        RECT  42.384 267.756 42.408 267.84 ;
    END
  END out_res[86]
  PIN out_res[87]
    DIRECTION OUTPUT ;
    USE SIGNAL ;
    PORT
      LAYER M5 ;
        RECT  42.624 267.756 42.648 267.84 ;
    END
  END out_res[87]
  PIN out_res[88]
    DIRECTION OUTPUT ;
    USE SIGNAL ;
    PORT
      LAYER M5 ;
        RECT  42.864 267.756 42.888 267.84 ;
    END
  END out_res[88]
  PIN out_res[89]
    DIRECTION OUTPUT ;
    USE SIGNAL ;
    PORT
      LAYER M5 ;
        RECT  43.104 267.756 43.128 267.84 ;
    END
  END out_res[89]
  PIN out_res[8]
    DIRECTION OUTPUT ;
    USE SIGNAL ;
    PORT
      LAYER M5 ;
        RECT  23.664 267.756 23.688 267.84 ;
    END
  END out_res[8]
  PIN out_res[90]
    DIRECTION OUTPUT ;
    USE SIGNAL ;
    PORT
      LAYER M5 ;
        RECT  43.344 267.756 43.368 267.84 ;
    END
  END out_res[90]
  PIN out_res[91]
    DIRECTION OUTPUT ;
    USE SIGNAL ;
    PORT
      LAYER M5 ;
        RECT  43.584 267.756 43.608 267.84 ;
    END
  END out_res[91]
  PIN out_res[92]
    DIRECTION OUTPUT ;
    USE SIGNAL ;
    PORT
      LAYER M5 ;
        RECT  43.824 267.756 43.848 267.84 ;
    END
  END out_res[92]
  PIN out_res[93]
    DIRECTION OUTPUT ;
    USE SIGNAL ;
    PORT
      LAYER M5 ;
        RECT  44.064 267.756 44.088 267.84 ;
    END
  END out_res[93]
  PIN out_res[94]
    DIRECTION OUTPUT ;
    USE SIGNAL ;
    PORT
      LAYER M5 ;
        RECT  44.304 267.756 44.328 267.84 ;
    END
  END out_res[94]
  PIN out_res[95]
    DIRECTION OUTPUT ;
    USE SIGNAL ;
    PORT
      LAYER M5 ;
        RECT  44.544 267.756 44.568 267.84 ;
    END
  END out_res[95]
  PIN out_res[96]
    DIRECTION OUTPUT ;
    USE SIGNAL ;
    PORT
      LAYER M5 ;
        RECT  44.784 267.756 44.808 267.84 ;
    END
  END out_res[96]
  PIN out_res[97]
    DIRECTION OUTPUT ;
    USE SIGNAL ;
    PORT
      LAYER M5 ;
        RECT  45.024 267.756 45.048 267.84 ;
    END
  END out_res[97]
  PIN out_res[98]
    DIRECTION OUTPUT ;
    USE SIGNAL ;
    PORT
      LAYER M5 ;
        RECT  45.264 267.756 45.288 267.84 ;
    END
  END out_res[98]
  PIN out_res[99]
    DIRECTION OUTPUT ;
    USE SIGNAL ;
    PORT
      LAYER M5 ;
        RECT  45.504 267.756 45.528 267.84 ;
    END
  END out_res[99]
  PIN out_res[9]
    DIRECTION OUTPUT ;
    USE SIGNAL ;
    PORT
      LAYER M5 ;
        RECT  23.904 267.756 23.928 267.84 ;
    END
  END out_res[9]
  PIN VDD
    DIRECTION INOUT ;
    USE POWER ;
    PORT
      LAYER M5 ;
        RECT  157.716 4.311 157.836 263.529 ;
        RECT  153.396 4.311 153.516 263.529 ;
        RECT  149.076 4.311 149.196 263.529 ;
        RECT  144.756 4.311 144.876 263.529 ;
        RECT  140.436 4.311 140.556 263.529 ;
        RECT  136.116 4.311 136.236 263.529 ;
        RECT  131.796 4.311 131.916 263.529 ;
        RECT  127.476 4.311 127.596 263.529 ;
        RECT  123.156 4.311 123.276 263.529 ;
        RECT  118.836 4.311 118.956 263.529 ;
        RECT  114.516 4.311 114.636 263.529 ;
        RECT  110.196 4.311 110.316 263.529 ;
        RECT  105.876 4.311 105.996 263.529 ;
        RECT  101.556 4.311 101.676 263.529 ;
        RECT  97.236 4.311 97.356 263.529 ;
        RECT  92.916 4.311 93.036 263.529 ;
        RECT  88.596 4.311 88.716 263.529 ;
        RECT  84.276 4.311 84.396 263.529 ;
        RECT  79.956 4.311 80.076 263.529 ;
        RECT  75.636 4.311 75.756 263.529 ;
        RECT  71.316 4.311 71.436 263.529 ;
        RECT  66.996 4.311 67.116 263.529 ;
        RECT  62.676 4.311 62.796 263.529 ;
        RECT  58.356 4.311 58.476 263.529 ;
        RECT  54.036 4.311 54.156 263.529 ;
        RECT  49.716 4.311 49.836 263.529 ;
        RECT  45.396 4.311 45.516 263.529 ;
        RECT  41.076 4.311 41.196 263.529 ;
        RECT  36.756 4.311 36.876 263.529 ;
        RECT  32.436 4.311 32.556 263.529 ;
        RECT  28.116 4.311 28.236 263.529 ;
        RECT  23.796 4.311 23.916 263.529 ;
        RECT  19.476 4.311 19.596 263.529 ;
        RECT  15.156 4.311 15.276 263.529 ;
        RECT  10.836 4.311 10.956 263.529 ;
        RECT  6.516 4.311 6.636 263.529 ;
    END
  END VDD
  PIN VSS
    DIRECTION INOUT ;
    USE GROUND ;
    PORT
      LAYER M5 ;
        RECT  157.524 4.297 157.644 263.543 ;
        RECT  153.204 4.297 153.324 263.543 ;
        RECT  148.884 4.297 149.004 263.543 ;
        RECT  144.564 4.297 144.684 263.543 ;
        RECT  140.244 4.297 140.364 263.543 ;
        RECT  135.924 4.297 136.044 263.543 ;
        RECT  131.604 4.297 131.724 263.543 ;
        RECT  127.284 4.297 127.404 263.543 ;
        RECT  122.964 4.297 123.084 263.543 ;
        RECT  118.644 4.297 118.764 263.543 ;
        RECT  114.324 4.297 114.444 263.543 ;
        RECT  110.004 4.297 110.124 263.543 ;
        RECT  105.684 4.297 105.804 263.543 ;
        RECT  101.364 4.297 101.484 263.543 ;
        RECT  97.044 4.297 97.164 263.543 ;
        RECT  92.724 4.297 92.844 263.543 ;
        RECT  88.404 4.297 88.524 263.543 ;
        RECT  84.084 4.297 84.204 263.543 ;
        RECT  79.764 4.297 79.884 263.543 ;
        RECT  75.444 4.297 75.564 263.543 ;
        RECT  71.124 4.297 71.244 263.543 ;
        RECT  66.804 4.297 66.924 263.543 ;
        RECT  62.484 4.297 62.604 263.543 ;
        RECT  58.164 4.297 58.284 263.543 ;
        RECT  53.844 4.297 53.964 263.543 ;
        RECT  49.524 4.297 49.644 263.543 ;
        RECT  45.204 4.297 45.324 263.543 ;
        RECT  40.884 4.297 41.004 263.543 ;
        RECT  36.564 4.297 36.684 263.543 ;
        RECT  32.244 4.297 32.364 263.543 ;
        RECT  27.924 4.297 28.044 263.543 ;
        RECT  23.604 4.297 23.724 263.543 ;
        RECT  19.284 4.297 19.404 263.543 ;
        RECT  14.964 4.297 15.084 263.543 ;
        RECT  10.644 4.297 10.764 263.543 ;
        RECT  6.324 4.297 6.444 263.543 ;
    END
  END VSS
  OBS
    LAYER RVTN ;
     RECT  0 4.297 159.899 267.84 ;
    LAYER RVTP ;
     RECT  0 4.297 159.899 267.84 ;
    LAYER M1 ;
     RECT  0 4.297 159.899 267.84 ;
    LAYER M2 ;
     RECT  0 4.297 159.899 267.84 ;
    LAYER M3 ;
     RECT  0 4.297 159.899 267.84 ;
    LAYER M4 ;
     RECT  0 4.297 159.899 267.84 ;
    LAYER M5 ;
     RECT  0 4.297 159.899 267.84 ;
  END
END dsdv_eng_rr_h1
END LIBRARY
